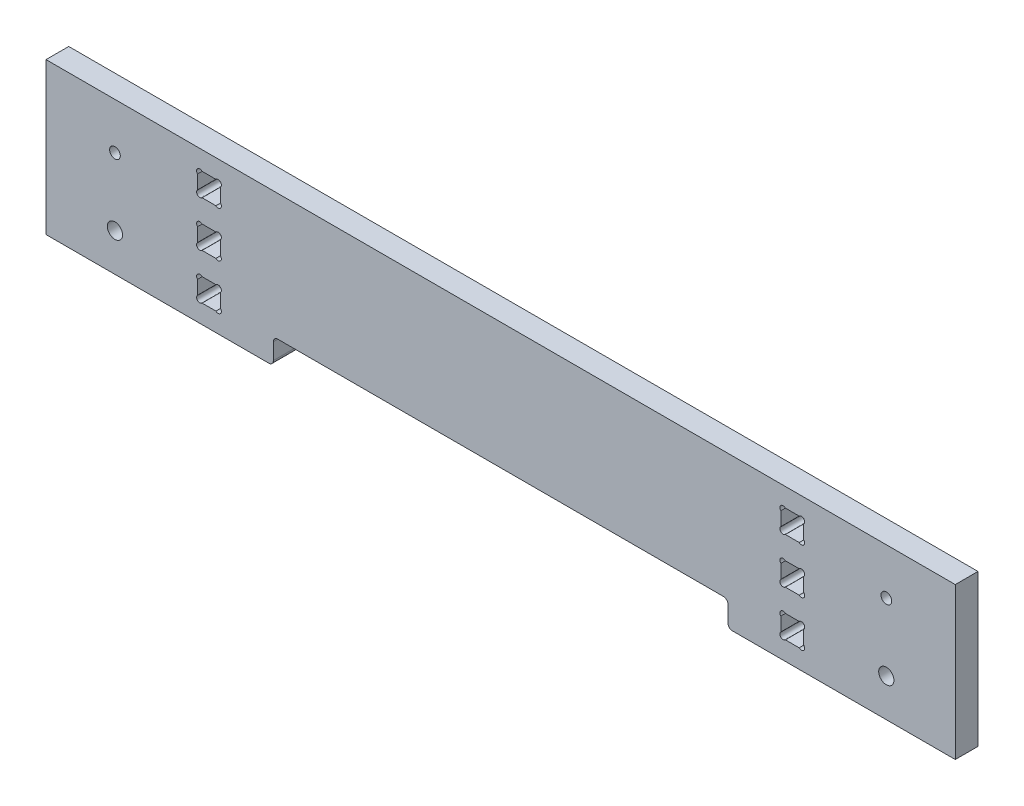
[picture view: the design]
ISO-10303-21;
HEADER;
FILE_DESCRIPTION(('STEP AP214'),'2;1');
FILE_NAME('part.step','',(''),(''),'','','');
FILE_SCHEMA(('AUTOMOTIVE_DESIGN { 1 0 10303 214 1 1 1 1 }'));
ENDSEC;
DATA;
#1=APPLICATION_CONTEXT('core data for automotive mechanical design processes');
#2=APPLICATION_PROTOCOL_DEFINITION('international standard','automotive_design',2000,#1);
#3=PRODUCT_CONTEXT('',#1,'mechanical');
#4=PRODUCT('Part','Part','',(#3));
#5=PRODUCT_RELATED_PRODUCT_CATEGORY('part','',(#4));
#6=PRODUCT_DEFINITION_FORMATION('','',#4);
#7=PRODUCT_DEFINITION_CONTEXT('part definition',#1,'design');
#8=PRODUCT_DEFINITION('design','',#6,#7);
#9=PRODUCT_DEFINITION_SHAPE('','',#8);
#10=(LENGTH_UNIT() NAMED_UNIT(*) SI_UNIT(.MILLI.,.METRE.));
#11=(NAMED_UNIT(*) PLANE_ANGLE_UNIT() SI_UNIT($,.RADIAN.));
#12=(NAMED_UNIT(*) SI_UNIT($,.STERADIAN.) SOLID_ANGLE_UNIT());
#13=UNCERTAINTY_MEASURE_WITH_UNIT(LENGTH_MEASURE(1.E-05),#10,'distance_accuracy_value','');
#14=(GEOMETRIC_REPRESENTATION_CONTEXT(3) GLOBAL_UNCERTAINTY_ASSIGNED_CONTEXT((#13)) GLOBAL_UNIT_ASSIGNED_CONTEXT((#10,
#11,#12)) REPRESENTATION_CONTEXT('',''));
#15=CARTESIAN_POINT('',(0.,0.,0.));
#16=DIRECTION('',(0.,0.,1.));
#17=DIRECTION('',(1.,0.,0.));
#18=AXIS2_PLACEMENT_3D('',#15,#16,#17);
#19=CARTESIAN_POINT('',(0.,0.,15.));
#20=DIRECTION('',(0.,0.,-1.));
#21=DIRECTION('',(-1.,0.,0.));
#22=AXIS2_PLACEMENT_3D('',#19,#20,#21);
#23=PLANE('',#22);
#24=CARTESIAN_POINT('',(45.5,25.,15.));
#25=DIRECTION('',(0.,0.,1.));
#26=DIRECTION('',(1.,0.,0.));
#27=AXIS2_PLACEMENT_3D('',#24,#25,#26);
#28=CIRCLE('',#27,5.025);
#29=CARTESIAN_POINT('',(50.5249999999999,25.,15.));
#30=VERTEX_POINT('',#29);
#31=EDGE_CURVE('E1713',#30,#30,#28,.T.);
#32=ORIENTED_EDGE('',*,*,#31,.F.);
#33=EDGE_LOOP('',(#32));
#34=FACE_BOUND('',#33,.T.);
#35=CARTESIAN_POINT('',(554.5,25.,15.));
#36=DIRECTION('',(0.,0.,1.));
#37=DIRECTION('',(1.,0.,0.));
#38=AXIS2_PLACEMENT_3D('',#35,#36,#37);
#39=CIRCLE('',#38,5.025);
#40=CARTESIAN_POINT('',(559.525,25.,15.));
#41=VERTEX_POINT('',#40);
#42=EDGE_CURVE('E1707',#41,#41,#39,.T.);
#43=ORIENTED_EDGE('',*,*,#42,.F.);
#44=EDGE_LOOP('',(#43));
#45=FACE_BOUND('',#44,.T.);
#46=CARTESIAN_POINT('',(554.5,69.5,15.));
#47=DIRECTION('',(0.,0.,1.));
#48=DIRECTION('',(1.,0.,0.));
#49=AXIS2_PLACEMENT_3D('',#46,#47,#48);
#50=CIRCLE('',#49,3.52500000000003);
#51=CARTESIAN_POINT('',(558.025,69.5,15.));
#52=VERTEX_POINT('',#51);
#53=EDGE_CURVE('E424',#52,#52,#50,.T.);
#54=ORIENTED_EDGE('',*,*,#53,.F.);
#55=EDGE_LOOP('',(#54));
#56=FACE_BOUND('',#55,.T.);
#57=DIRECTION('',(-1.,0.,0.));
#58=VECTOR('',#57,1.);
#59=CARTESIAN_POINT('',(112.1,27.4500000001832,15.));
#60=LINE('',#59,#58);
#61=CARTESIAN_POINT('',(112.1,27.4500000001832,15.));
#62=VERTEX_POINT('',#61);
#63=CARTESIAN_POINT('',(103.,27.4500000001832,15.));
#64=VERTEX_POINT('',#63);
#65=EDGE_CURVE('E438',#62,#64,#60,.T.);
#66=ORIENTED_EDGE('',*,*,#65,.F.);
#67=CARTESIAN_POINT('',(113.6,25.9500000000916,15.));
#68=DIRECTION('',(0.,0.,1.));
#69=DIRECTION('',(1.,0.,0.));
#70=AXIS2_PLACEMENT_3D('',#67,#68,#69);
#71=CIRCLE('',#70,2.12132034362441);
#72=CARTESIAN_POINT('',(115.1,24.45,15.));
#73=VERTEX_POINT('',#72);
#74=EDGE_CURVE('E416',#73,#62,#71,.T.);
#75=ORIENTED_EDGE('',*,*,#74,.F.);
#76=DIRECTION('',(0.,1.,0.));
#77=VECTOR('',#76,1.);
#78=CARTESIAN_POINT('',(115.1,15.35,15.));
#79=LINE('',#78,#77);
#80=CARTESIAN_POINT('',(115.1,15.35,15.));
#81=VERTEX_POINT('',#80);
#82=EDGE_CURVE('E427',#81,#73,#79,.T.);
#83=ORIENTED_EDGE('',*,*,#82,.F.);
#84=CARTESIAN_POINT('',(113.6,13.85,15.));
#85=DIRECTION('',(0.,0.,1.));
#86=DIRECTION('',(1.,0.,0.));
#87=AXIS2_PLACEMENT_3D('',#84,#85,#86);
#88=CIRCLE('',#87,2.12132034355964);
#89=CARTESIAN_POINT('',(112.1,12.35,15.));
#90=VERTEX_POINT('',#89);
#91=EDGE_CURVE('E432',#90,#81,#88,.T.);
#92=ORIENTED_EDGE('',*,*,#91,.F.);
#93=DIRECTION('',(1.,0.,0.));
#94=VECTOR('',#93,1.);
#95=CARTESIAN_POINT('',(103.,12.35,15.));
#96=LINE('',#95,#94);
#97=CARTESIAN_POINT('',(103.,12.35,15.));
#98=VERTEX_POINT('',#97);
#99=EDGE_CURVE('E1671',#98,#90,#96,.T.);
#100=ORIENTED_EDGE('',*,*,#99,.F.);
#101=CARTESIAN_POINT('',(101.5,13.85,15.));
#102=DIRECTION('',(0.,0.,1.));
#103=DIRECTION('',(1.,0.,0.));
#104=AXIS2_PLACEMENT_3D('',#101,#102,#103);
#105=CIRCLE('',#104,2.12132034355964);
#106=CARTESIAN_POINT('',(100.,15.35,15.));
#107=VERTEX_POINT('',#106);
#108=EDGE_CURVE('E1673',#107,#98,#105,.T.);
#109=ORIENTED_EDGE('',*,*,#108,.F.);
#110=DIRECTION('',(0.,-1.,0.));
#111=VECTOR('',#110,1.);
#112=CARTESIAN_POINT('',(100.,24.45,15.));
#113=LINE('',#112,#111);
#114=CARTESIAN_POINT('',(100.,24.45,15.));
#115=VERTEX_POINT('',#114);
#116=EDGE_CURVE('E1678',#115,#107,#113,.T.);
#117=ORIENTED_EDGE('',*,*,#116,.F.);
#118=CARTESIAN_POINT('',(101.5,25.9500000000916,15.));
#119=DIRECTION('',(0.,0.,-1.));
#120=DIRECTION('',(-1.,0.,0.));
#121=AXIS2_PLACEMENT_3D('',#118,#119,#120);
#122=CIRCLE('',#121,2.12132034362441);
#123=EDGE_CURVE('E443',#115,#64,#122,.T.);
#124=ORIENTED_EDGE('',*,*,#123,.T.);
#125=EDGE_LOOP('',(#66,#75,#83,#92,#100,#109,#117,#124));
#126=FACE_BOUND('',#125,.T.);
#127=CARTESIAN_POINT('',(113.6,43.9500000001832,15.));
#128=DIRECTION('',(0.,0.,1.));
#129=DIRECTION('',(1.,0.,0.));
#130=AXIS2_PLACEMENT_3D('',#127,#128,#129);
#131=CIRCLE('',#130,2.12132034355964);
#132=CARTESIAN_POINT('',(112.1,42.4500000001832,15.));
#133=VERTEX_POINT('',#132);
#134=CARTESIAN_POINT('',(115.1,45.4500000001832,15.));
#135=VERTEX_POINT('',#134);
#136=EDGE_CURVE('E503',#133,#135,#131,.T.);
#137=ORIENTED_EDGE('',*,*,#136,.F.);
#138=DIRECTION('',(1.,0.,0.));
#139=VECTOR('',#138,1.);
#140=CARTESIAN_POINT('',(103.,42.4500000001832,15.));
#141=LINE('',#140,#139);
#142=CARTESIAN_POINT('',(103.,42.4500000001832,15.));
#143=VERTEX_POINT('',#142);
#144=EDGE_CURVE('E506',#143,#133,#141,.T.);
#145=ORIENTED_EDGE('',*,*,#144,.F.);
#146=CARTESIAN_POINT('',(101.5,43.9500000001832,15.));
#147=DIRECTION('',(0.,0.,1.));
#148=DIRECTION('',(1.,0.,0.));
#149=AXIS2_PLACEMENT_3D('',#146,#147,#148);
#150=CIRCLE('',#149,2.12132034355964);
#151=CARTESIAN_POINT('',(100.,45.4500000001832,15.));
#152=VERTEX_POINT('',#151);
#153=EDGE_CURVE('E484',#152,#143,#150,.T.);
#154=ORIENTED_EDGE('',*,*,#153,.F.);
#155=DIRECTION('',(0.,-1.,0.));
#156=VECTOR('',#155,1.);
#157=CARTESIAN_POINT('',(100.,54.5500000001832,15.));
#158=LINE('',#157,#156);
#159=CARTESIAN_POINT('',(100.,54.5500000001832,15.));
#160=VERTEX_POINT('',#159);
#161=EDGE_CURVE('E487',#160,#152,#158,.T.);
#162=ORIENTED_EDGE('',*,*,#161,.F.);
#163=CARTESIAN_POINT('',(101.5,56.0500000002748,15.));
#164=DIRECTION('',(0.,0.,-1.));
#165=DIRECTION('',(-1.,0.,0.));
#166=AXIS2_PLACEMENT_3D('',#163,#164,#165);
#167=CIRCLE('',#166,2.1213203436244);
#168=CARTESIAN_POINT('',(103.,57.5500000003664,15.));
#169=VERTEX_POINT('',#168);
#170=EDGE_CURVE('E491',#160,#169,#167,.T.);
#171=ORIENTED_EDGE('',*,*,#170,.T.);
#172=DIRECTION('',(-1.,0.,0.));
#173=VECTOR('',#172,1.);
#174=CARTESIAN_POINT('',(112.1,57.5500000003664,15.));
#175=LINE('',#174,#173);
#176=CARTESIAN_POINT('',(112.1,57.5500000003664,15.));
#177=VERTEX_POINT('',#176);
#178=EDGE_CURVE('E494',#177,#169,#175,.T.);
#179=ORIENTED_EDGE('',*,*,#178,.F.);
#180=CARTESIAN_POINT('',(113.6,56.0500000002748,15.));
#181=DIRECTION('',(0.,0.,1.));
#182=DIRECTION('',(1.,0.,0.));
#183=AXIS2_PLACEMENT_3D('',#180,#181,#182);
#184=CIRCLE('',#183,2.12132034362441);
#185=CARTESIAN_POINT('',(115.1,54.5500000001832,15.));
#186=VERTEX_POINT('',#185);
#187=EDGE_CURVE('E497',#186,#177,#184,.T.);
#188=ORIENTED_EDGE('',*,*,#187,.F.);
#189=DIRECTION('',(0.,1.,0.));
#190=VECTOR('',#189,1.);
#191=CARTESIAN_POINT('',(115.1,45.4500000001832,15.));
#192=LINE('',#191,#190);
#193=EDGE_CURVE('E500',#135,#186,#192,.T.);
#194=ORIENTED_EDGE('',*,*,#193,.F.);
#195=EDGE_LOOP('',(#137,#145,#154,#162,#171,#179,#188,#194));
#196=FACE_BOUND('',#195,.T.);
#197=DIRECTION('',(1.,0.,0.));
#198=VECTOR('',#197,1.);
#199=CARTESIAN_POINT('',(103.,72.5500000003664,15.));
#200=LINE('',#199,#198);
#201=CARTESIAN_POINT('',(103.,72.5500000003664,15.));
#202=VERTEX_POINT('',#201);
#203=CARTESIAN_POINT('',(112.1,72.5500000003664,15.));
#204=VERTEX_POINT('',#203);
#205=EDGE_CURVE('E566',#202,#204,#200,.T.);
#206=ORIENTED_EDGE('',*,*,#205,.F.);
#207=CARTESIAN_POINT('',(101.5,74.0500000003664,15.));
#208=DIRECTION('',(0.,0.,1.));
#209=DIRECTION('',(1.,0.,0.));
#210=AXIS2_PLACEMENT_3D('',#207,#208,#209);
#211=CIRCLE('',#210,2.12132034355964);
#212=CARTESIAN_POINT('',(100.,75.5500000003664,15.));
#213=VERTEX_POINT('',#212);
#214=EDGE_CURVE('E569',#213,#202,#211,.T.);
#215=ORIENTED_EDGE('',*,*,#214,.F.);
#216=DIRECTION('',(0.,-1.,0.));
#217=VECTOR('',#216,1.);
#218=CARTESIAN_POINT('',(100.,84.6500000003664,15.));
#219=LINE('',#218,#217);
#220=CARTESIAN_POINT('',(100.,84.6500000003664,15.));
#221=VERTEX_POINT('',#220);
#222=EDGE_CURVE('E547',#221,#213,#219,.T.);
#223=ORIENTED_EDGE('',*,*,#222,.F.);
#224=CARTESIAN_POINT('',(101.5,86.150000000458,15.));
#225=DIRECTION('',(0.,0.,-1.));
#226=DIRECTION('',(-1.,0.,0.));
#227=AXIS2_PLACEMENT_3D('',#224,#225,#226);
#228=CIRCLE('',#227,2.12132034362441);
#229=CARTESIAN_POINT('',(103.,87.6500000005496,15.));
#230=VERTEX_POINT('',#229);
#231=EDGE_CURVE('E550',#221,#230,#228,.T.);
#232=ORIENTED_EDGE('',*,*,#231,.T.);
#233=DIRECTION('',(-1.,0.,0.));
#234=VECTOR('',#233,1.);
#235=CARTESIAN_POINT('',(112.1,87.6500000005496,15.));
#236=LINE('',#235,#234);
#237=CARTESIAN_POINT('',(112.1,87.6500000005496,15.));
#238=VERTEX_POINT('',#237);
#239=EDGE_CURVE('E554',#238,#230,#236,.T.);
#240=ORIENTED_EDGE('',*,*,#239,.F.);
#241=CARTESIAN_POINT('',(113.6,86.150000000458,15.));
#242=DIRECTION('',(0.,0.,1.));
#243=DIRECTION('',(1.,0.,0.));
#244=AXIS2_PLACEMENT_3D('',#241,#242,#243);
#245=CIRCLE('',#244,2.12132034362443);
#246=CARTESIAN_POINT('',(115.1,84.6500000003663,15.));
#247=VERTEX_POINT('',#246);
#248=EDGE_CURVE('E557',#247,#238,#245,.T.);
#249=ORIENTED_EDGE('',*,*,#248,.F.);
#250=DIRECTION('',(0.,1.,0.));
#251=VECTOR('',#250,1.);
#252=CARTESIAN_POINT('',(115.1,75.5500000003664,15.));
#253=LINE('',#252,#251);
#254=CARTESIAN_POINT('',(115.1,75.5500000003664,15.));
#255=VERTEX_POINT('',#254);
#256=EDGE_CURVE('E560',#255,#247,#253,.T.);
#257=ORIENTED_EDGE('',*,*,#256,.F.);
#258=CARTESIAN_POINT('',(113.6,74.0500000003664,15.));
#259=DIRECTION('',(0.,0.,1.));
#260=DIRECTION('',(1.,0.,0.));
#261=AXIS2_PLACEMENT_3D('',#258,#259,#260);
#262=CIRCLE('',#261,2.12132034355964);
#263=EDGE_CURVE('E563',#204,#255,#262,.T.);
#264=ORIENTED_EDGE('',*,*,#263,.F.);
#265=EDGE_LOOP('',(#206,#215,#223,#232,#240,#249,#257,#264));
#266=FACE_BOUND('',#265,.T.);
#267=CARTESIAN_POINT('',(45.5,69.5,15.));
#268=DIRECTION('',(0.,0.,1.));
#269=DIRECTION('',(1.,0.,0.));
#270=AXIS2_PLACEMENT_3D('',#267,#268,#269);
#271=CIRCLE('',#270,3.525);
#272=CARTESIAN_POINT('',(49.025,69.5,15.));
#273=VERTEX_POINT('',#272);
#274=EDGE_CURVE('E593',#273,#273,#271,.T.);
#275=ORIENTED_EDGE('',*,*,#274,.F.);
#276=EDGE_LOOP('',(#275));
#277=FACE_BOUND('',#276,.T.);
#278=CARTESIAN_POINT('',(498.5,56.0499999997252,15.));
#279=DIRECTION('',(0.,0.,1.));
#280=DIRECTION('',(1.,0.,0.));
#281=AXIS2_PLACEMENT_3D('',#278,#279,#280);
#282=CIRCLE('',#281,2.12132034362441);
#283=CARTESIAN_POINT('',(500.,54.5499999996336,15.));
#284=VERTEX_POINT('',#283);
#285=CARTESIAN_POINT('',(497.,57.5499999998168,15.));
#286=VERTEX_POINT('',#285);
#287=EDGE_CURVE('E635',#284,#286,#282,.T.);
#288=ORIENTED_EDGE('',*,*,#287,.F.);
#289=DIRECTION('',(0.,1.,0.));
#290=VECTOR('',#289,1.);
#291=CARTESIAN_POINT('',(500.,0.,15.));
#292=LINE('',#291,#290);
#293=CARTESIAN_POINT('',(500.,45.4499999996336,15.));
#294=VERTEX_POINT('',#293);
#295=EDGE_CURVE('E638',#294,#284,#292,.T.);
#296=ORIENTED_EDGE('',*,*,#295,.F.);
#297=CARTESIAN_POINT('',(498.5,43.9499999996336,15.));
#298=DIRECTION('',(0.,0.,1.));
#299=DIRECTION('',(1.,0.,0.));
#300=AXIS2_PLACEMENT_3D('',#297,#298,#299);
#301=CIRCLE('',#300,2.12132034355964);
#302=CARTESIAN_POINT('',(497.,42.4499999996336,15.));
#303=VERTEX_POINT('',#302);
#304=EDGE_CURVE('E616',#303,#294,#301,.T.);
#305=ORIENTED_EDGE('',*,*,#304,.F.);
#306=DIRECTION('',(1.,0.,0.));
#307=VECTOR('',#306,1.);
#308=CARTESIAN_POINT('',(0.,42.4499999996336,15.));
#309=LINE('',#308,#307);
#310=CARTESIAN_POINT('',(487.9,42.4499999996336,15.));
#311=VERTEX_POINT('',#310);
#312=EDGE_CURVE('E619',#311,#303,#309,.T.);
#313=ORIENTED_EDGE('',*,*,#312,.F.);
#314=CARTESIAN_POINT('',(486.4,43.9499999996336,15.));
#315=DIRECTION('',(0.,0.,1.));
#316=DIRECTION('',(1.,0.,0.));
#317=AXIS2_PLACEMENT_3D('',#314,#315,#316);
#318=CIRCLE('',#317,2.12132034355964);
#319=CARTESIAN_POINT('',(484.9,45.4499999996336,15.));
#320=VERTEX_POINT('',#319);
#321=EDGE_CURVE('E623',#320,#311,#318,.T.);
#322=ORIENTED_EDGE('',*,*,#321,.F.);
#323=DIRECTION('',(0.,-1.,0.));
#324=VECTOR('',#323,1.);
#325=CARTESIAN_POINT('',(484.9,0.,15.));
#326=LINE('',#325,#324);
#327=CARTESIAN_POINT('',(484.9,54.5499999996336,15.));
#328=VERTEX_POINT('',#327);
#329=EDGE_CURVE('E626',#328,#320,#326,.T.);
#330=ORIENTED_EDGE('',*,*,#329,.F.);
#331=CARTESIAN_POINT('',(486.4,56.0499999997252,15.));
#332=DIRECTION('',(0.,0.,1.));
#333=DIRECTION('',(1.,0.,0.));
#334=AXIS2_PLACEMENT_3D('',#331,#332,#333);
#335=CIRCLE('',#334,2.12132034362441);
#336=CARTESIAN_POINT('',(487.9,57.5499999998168,15.));
#337=VERTEX_POINT('',#336);
#338=EDGE_CURVE('E629',#328,#337,#335,.F.);
#339=ORIENTED_EDGE('',*,*,#338,.T.);
#340=DIRECTION('',(-1.,0.,0.));
#341=VECTOR('',#340,1.);
#342=CARTESIAN_POINT('',(0.,57.5499999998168,15.));
#343=LINE('',#342,#341);
#344=EDGE_CURVE('E632',#286,#337,#343,.T.);
#345=ORIENTED_EDGE('',*,*,#344,.F.);
#346=EDGE_LOOP('',(#288,#296,#305,#313,#322,#330,#339,#345));
#347=FACE_BOUND('',#346,.T.);
#348=CARTESIAN_POINT('',(498.5,25.9499999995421,15.));
#349=DIRECTION('',(0.,0.,1.));
#350=DIRECTION('',(1.,0.,0.));
#351=AXIS2_PLACEMENT_3D('',#348,#349,#350);
#352=CIRCLE('',#351,2.12132034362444);
#353=CARTESIAN_POINT('',(500.,24.4499999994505,15.));
#354=VERTEX_POINT('',#353);
#355=CARTESIAN_POINT('',(497.,27.4499999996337,15.));
#356=VERTEX_POINT('',#355);
#357=EDGE_CURVE('E698',#354,#356,#352,.T.);
#358=ORIENTED_EDGE('',*,*,#357,.F.);
#359=DIRECTION('',(0.,1.,0.));
#360=VECTOR('',#359,1.);
#361=CARTESIAN_POINT('',(500.,0.,15.));
#362=LINE('',#361,#360);
#363=CARTESIAN_POINT('',(500.,15.3499999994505,15.));
#364=VERTEX_POINT('',#363);
#365=EDGE_CURVE('E701',#364,#354,#362,.T.);
#366=ORIENTED_EDGE('',*,*,#365,.F.);
#367=CARTESIAN_POINT('',(498.5,13.8499999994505,15.));
#368=DIRECTION('',(0.,0.,1.));
#369=DIRECTION('',(1.,0.,0.));
#370=AXIS2_PLACEMENT_3D('',#367,#368,#369);
#371=CIRCLE('',#370,2.12132034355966);
#372=CARTESIAN_POINT('',(497.,12.3499999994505,15.));
#373=VERTEX_POINT('',#372);
#374=EDGE_CURVE('E679',#373,#364,#371,.T.);
#375=ORIENTED_EDGE('',*,*,#374,.F.);
#376=DIRECTION('',(1.,0.,0.));
#377=VECTOR('',#376,1.);
#378=CARTESIAN_POINT('',(0.,12.3499999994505,15.));
#379=LINE('',#378,#377);
#380=CARTESIAN_POINT('',(487.9,12.3499999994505,15.));
#381=VERTEX_POINT('',#380);
#382=EDGE_CURVE('E682',#381,#373,#379,.T.);
#383=ORIENTED_EDGE('',*,*,#382,.F.);
#384=CARTESIAN_POINT('',(486.4,13.8499999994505,15.));
#385=DIRECTION('',(0.,0.,1.));
#386=DIRECTION('',(1.,0.,0.));
#387=AXIS2_PLACEMENT_3D('',#384,#385,#386);
#388=CIRCLE('',#387,2.12132034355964);
#389=CARTESIAN_POINT('',(484.9,15.3499999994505,15.));
#390=VERTEX_POINT('',#389);
#391=EDGE_CURVE('E686',#390,#381,#388,.T.);
#392=ORIENTED_EDGE('',*,*,#391,.F.);
#393=DIRECTION('',(0.,-1.,0.));
#394=VECTOR('',#393,1.);
#395=CARTESIAN_POINT('',(484.9,0.,15.));
#396=LINE('',#395,#394);
#397=CARTESIAN_POINT('',(484.9,24.4499999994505,15.));
#398=VERTEX_POINT('',#397);
#399=EDGE_CURVE('E689',#398,#390,#396,.T.);
#400=ORIENTED_EDGE('',*,*,#399,.F.);
#401=CARTESIAN_POINT('',(486.4,25.9499999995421,15.));
#402=DIRECTION('',(0.,0.,1.));
#403=DIRECTION('',(1.,0.,0.));
#404=AXIS2_PLACEMENT_3D('',#401,#402,#403);
#405=CIRCLE('',#404,2.12132034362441);
#406=CARTESIAN_POINT('',(487.9,27.4499999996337,15.));
#407=VERTEX_POINT('',#406);
#408=EDGE_CURVE('E692',#398,#407,#405,.F.);
#409=ORIENTED_EDGE('',*,*,#408,.T.);
#410=DIRECTION('',(-1.,0.,0.));
#411=VECTOR('',#410,1.);
#412=CARTESIAN_POINT('',(0.,27.4499999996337,15.));
#413=LINE('',#412,#411);
#414=EDGE_CURVE('E695',#356,#407,#413,.T.);
#415=ORIENTED_EDGE('',*,*,#414,.F.);
#416=EDGE_LOOP('',(#358,#366,#375,#383,#392,#400,#409,#415));
#417=FACE_BOUND('',#416,.T.);
#418=DIRECTION('',(0.,-1.,0.));
#419=VECTOR('',#418,1.);
#420=CARTESIAN_POINT('',(450.,16.7043263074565,15.));
#421=LINE('',#420,#419);
#422=CARTESIAN_POINT('',(450.,13.7043263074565,15.));
#423=VERTEX_POINT('',#422);
#424=CARTESIAN_POINT('',(450.,3.,15.));
#425=VERTEX_POINT('',#424);
#426=EDGE_CURVE('E799',#423,#425,#421,.T.);
#427=ORIENTED_EDGE('',*,*,#426,.T.);
#428=CARTESIAN_POINT('',(453.,3.,15.));
#429=DIRECTION('',(0.,0.,-1.));
#430=DIRECTION('',(-1.,0.,0.));
#431=AXIS2_PLACEMENT_3D('',#428,#429,#430);
#432=CIRCLE('',#431,3.);
#433=CARTESIAN_POINT('',(453.,0.,15.));
#434=VERTEX_POINT('',#433);
#435=EDGE_CURVE('E856',#425,#434,#432,.F.);
#436=ORIENTED_EDGE('',*,*,#435,.T.);
#437=DIRECTION('',(1.,0.,0.));
#438=VECTOR('',#437,1.);
#439=CARTESIAN_POINT('',(450.,0.,15.));
#440=LINE('',#439,#438);
#441=CARTESIAN_POINT('',(600.,0.,15.));
#442=VERTEX_POINT('',#441);
#443=EDGE_CURVE('E802',#434,#442,#440,.T.);
#444=ORIENTED_EDGE('',*,*,#443,.T.);
#445=DIRECTION('',(0.,1.,0.));
#446=VECTOR('',#445,1.);
#447=CARTESIAN_POINT('',(600.,0.,15.));
#448=LINE('',#447,#446);
#449=CARTESIAN_POINT('',(600.,100.,15.));
#450=VERTEX_POINT('',#449);
#451=EDGE_CURVE('E804',#442,#450,#448,.T.);
#452=ORIENTED_EDGE('',*,*,#451,.T.);
#453=DIRECTION('',(-1.,0.,0.));
#454=VECTOR('',#453,1.);
#455=CARTESIAN_POINT('',(0.,100.,15.));
#456=LINE('',#455,#454);
#457=CARTESIAN_POINT('',(0.,100.,15.));
#458=VERTEX_POINT('',#457);
#459=EDGE_CURVE('E806',#450,#458,#456,.T.);
#460=ORIENTED_EDGE('',*,*,#459,.T.);
#461=DIRECTION('',(0.,-1.,0.));
#462=VECTOR('',#461,1.);
#463=CARTESIAN_POINT('',(0.,0.,15.));
#464=LINE('',#463,#462);
#465=CARTESIAN_POINT('',(0.,0.,15.));
#466=VERTEX_POINT('',#465);
#467=EDGE_CURVE('E788',#458,#466,#464,.T.);
#468=ORIENTED_EDGE('',*,*,#467,.T.);
#469=DIRECTION('',(1.,0.,0.));
#470=VECTOR('',#469,1.);
#471=CARTESIAN_POINT('',(0.,0.,15.));
#472=LINE('',#471,#470);
#473=CARTESIAN_POINT('',(147.,0.,15.));
#474=VERTEX_POINT('',#473);
#475=EDGE_CURVE('E791',#466,#474,#472,.T.);
#476=ORIENTED_EDGE('',*,*,#475,.T.);
#477=CARTESIAN_POINT('',(147.,3.,15.));
#478=DIRECTION('',(0.,0.,-1.));
#479=DIRECTION('',(-1.,0.,0.));
#480=AXIS2_PLACEMENT_3D('',#477,#478,#479);
#481=CIRCLE('',#480,3.);
#482=CARTESIAN_POINT('',(150.,3.,15.));
#483=VERTEX_POINT('',#482);
#484=EDGE_CURVE('E57',#474,#483,#481,.F.);
#485=ORIENTED_EDGE('',*,*,#484,.T.);
#486=DIRECTION('',(0.,1.,0.));
#487=VECTOR('',#486,1.);
#488=CARTESIAN_POINT('',(150.,0.,15.));
#489=LINE('',#488,#487);
#490=CARTESIAN_POINT('',(150.,13.7043263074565,15.));
#491=VERTEX_POINT('',#490);
#492=EDGE_CURVE('E794',#483,#491,#489,.T.);
#493=ORIENTED_EDGE('',*,*,#492,.T.);
#494=CARTESIAN_POINT('',(153.,13.7043263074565,15.));
#495=DIRECTION('',(0.,0.,-1.));
#496=DIRECTION('',(-1.,0.,0.));
#497=AXIS2_PLACEMENT_3D('',#494,#495,#496);
#498=CIRCLE('',#497,3.);
#499=CARTESIAN_POINT('',(153.,16.7043263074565,15.));
#500=VERTEX_POINT('',#499);
#501=EDGE_CURVE('E11',#491,#500,#498,.T.);
#502=ORIENTED_EDGE('',*,*,#501,.T.);
#503=DIRECTION('',(1.,0.,0.));
#504=VECTOR('',#503,1.);
#505=CARTESIAN_POINT('',(150.,16.7043263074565,15.));
#506=LINE('',#505,#504);
#507=CARTESIAN_POINT('',(447.,16.7043263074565,15.));
#508=VERTEX_POINT('',#507);
#509=EDGE_CURVE('E796',#500,#508,#506,.T.);
#510=ORIENTED_EDGE('',*,*,#509,.T.);
#511=CARTESIAN_POINT('',(447.,13.7043263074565,15.));
#512=DIRECTION('',(0.,0.,-1.));
#513=DIRECTION('',(-1.,0.,0.));
#514=AXIS2_PLACEMENT_3D('',#511,#512,#513);
#515=CIRCLE('',#514,3.);
#516=EDGE_CURVE('E866',#508,#423,#515,.T.);
#517=ORIENTED_EDGE('',*,*,#516,.T.);
#518=EDGE_LOOP('',(#427,#436,#444,#452,#460,#468,#476,#485,#493,#502,#510,#517));
#519=FACE_BOUND('',#518,.T.);
#520=DIRECTION('',(0.,-1.,0.));
#521=VECTOR('',#520,1.);
#522=CARTESIAN_POINT('',(500.,0.,15.));
#523=LINE('',#522,#521);
#524=CARTESIAN_POINT('',(500.,84.6499999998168,15.));
#525=VERTEX_POINT('',#524);
#526=CARTESIAN_POINT('',(500.,75.5499999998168,15.));
#527=VERTEX_POINT('',#526);
#528=EDGE_CURVE('E703',#525,#527,#523,.T.);
#529=ORIENTED_EDGE('',*,*,#528,.T.);
#530=CARTESIAN_POINT('',(498.5,74.0499999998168,15.));
#531=DIRECTION('',(0.,0.,1.));
#532=DIRECTION('',(1.,0.,0.));
#533=AXIS2_PLACEMENT_3D('',#530,#531,#532);
#534=CIRCLE('',#533,2.12132034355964);
#535=CARTESIAN_POINT('',(497.,72.5499999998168,15.));
#536=VERTEX_POINT('',#535);
#537=EDGE_CURVE('E728',#536,#527,#534,.T.);
#538=ORIENTED_EDGE('',*,*,#537,.F.);
#539=DIRECTION('',(1.,0.,0.));
#540=VECTOR('',#539,1.);
#541=CARTESIAN_POINT('',(0.,72.5499999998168,15.));
#542=LINE('',#541,#540);
#543=CARTESIAN_POINT('',(487.9,72.5499999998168,15.));
#544=VERTEX_POINT('',#543);
#545=EDGE_CURVE('E766',#544,#536,#542,.T.);
#546=ORIENTED_EDGE('',*,*,#545,.F.);
#547=CARTESIAN_POINT('',(486.4,74.0499999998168,15.));
#548=DIRECTION('',(0.,0.,1.));
#549=DIRECTION('',(1.,0.,0.));
#550=AXIS2_PLACEMENT_3D('',#547,#548,#549);
#551=CIRCLE('',#550,2.12132034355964);
#552=CARTESIAN_POINT('',(484.9,75.5499999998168,15.));
#553=VERTEX_POINT('',#552);
#554=EDGE_CURVE('E763',#553,#544,#551,.T.);
#555=ORIENTED_EDGE('',*,*,#554,.F.);
#556=DIRECTION('',(0.,-1.,0.));
#557=VECTOR('',#556,1.);
#558=CARTESIAN_POINT('',(484.9,0.,15.));
#559=LINE('',#558,#557);
#560=CARTESIAN_POINT('',(484.9,84.6499999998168,15.));
#561=VERTEX_POINT('',#560);
#562=EDGE_CURVE('E760',#561,#553,#559,.T.);
#563=ORIENTED_EDGE('',*,*,#562,.F.);
#564=CARTESIAN_POINT('',(486.4,86.1499999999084,15.));
#565=DIRECTION('',(0.,0.,1.));
#566=DIRECTION('',(1.,0.,0.));
#567=AXIS2_PLACEMENT_3D('',#564,#565,#566);
#568=CIRCLE('',#567,2.12132034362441);
#569=CARTESIAN_POINT('',(487.9,87.65,15.));
#570=VERTEX_POINT('',#569);
#571=EDGE_CURVE('E757',#561,#570,#568,.F.);
#572=ORIENTED_EDGE('',*,*,#571,.T.);
#573=DIRECTION('',(-1.,0.,0.));
#574=VECTOR('',#573,1.);
#575=CARTESIAN_POINT('',(0.,87.65,15.));
#576=LINE('',#575,#574);
#577=CARTESIAN_POINT('',(497.,87.65,15.));
#578=VERTEX_POINT('',#577);
#579=EDGE_CURVE('E754',#578,#570,#576,.T.);
#580=ORIENTED_EDGE('',*,*,#579,.F.);
#581=CARTESIAN_POINT('',(498.5,86.1499999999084,15.));
#582=DIRECTION('',(0.,0.,1.));
#583=DIRECTION('',(1.,0.,0.));
#584=AXIS2_PLACEMENT_3D('',#581,#582,#583);
#585=CIRCLE('',#584,2.12132034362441);
#586=EDGE_CURVE('E751',#525,#578,#585,.T.);
#587=ORIENTED_EDGE('',*,*,#586,.F.);
#588=EDGE_LOOP('',(#529,#538,#546,#555,#563,#572,#580,#587));
#589=FACE_BOUND('',#588,.T.);
#590=ADVANCED_FACE('F35',(#34,#45,#56,#126,#196,#266,#277,#347,#417,#519,#589),#23,.F.);
#591=CARTESIAN_POINT('',(0.,0.,0.));
#592=DIRECTION('',(0.,0.,-1.));
#593=DIRECTION('',(-1.,0.,0.));
#594=AXIS2_PLACEMENT_3D('',#591,#592,#593);
#595=PLANE('',#594);
#596=CARTESIAN_POINT('',(554.5,69.5,0.));
#597=DIRECTION('',(0.,0.,1.));
#598=DIRECTION('',(1.,0.,0.));
#599=AXIS2_PLACEMENT_3D('',#596,#597,#598);
#600=CIRCLE('',#599,3.52500000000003);
#601=CARTESIAN_POINT('',(558.025,69.5,0.));
#602=VERTEX_POINT('',#601);
#603=EDGE_CURVE('E1691',#602,#602,#600,.T.);
#604=ORIENTED_EDGE('',*,*,#603,.T.);
#605=EDGE_LOOP('',(#604));
#606=FACE_BOUND('',#605,.T.);
#607=CARTESIAN_POINT('',(113.6,25.9500000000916,0.));
#608=DIRECTION('',(0.,0.,1.));
#609=DIRECTION('',(1.,0.,0.));
#610=AXIS2_PLACEMENT_3D('',#607,#608,#609);
#611=CIRCLE('',#610,2.12132034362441);
#612=CARTESIAN_POINT('',(115.1,24.45,0.));
#613=VERTEX_POINT('',#612);
#614=CARTESIAN_POINT('',(112.1,27.4500000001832,0.));
#615=VERTEX_POINT('',#614);
#616=EDGE_CURVE('E419',#613,#615,#611,.T.);
#617=ORIENTED_EDGE('',*,*,#616,.T.);
#618=DIRECTION('',(-1.,0.,0.));
#619=VECTOR('',#618,1.);
#620=CARTESIAN_POINT('',(112.1,27.4500000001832,0.));
#621=LINE('',#620,#619);
#622=CARTESIAN_POINT('',(103.,27.4500000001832,0.));
#623=VERTEX_POINT('',#622);
#624=EDGE_CURVE('E465',#615,#623,#621,.T.);
#625=ORIENTED_EDGE('',*,*,#624,.T.);
#626=CARTESIAN_POINT('',(101.5,25.9500000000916,0.));
#627=DIRECTION('',(0.,0.,-1.));
#628=DIRECTION('',(-1.,0.,0.));
#629=AXIS2_PLACEMENT_3D('',#626,#627,#628);
#630=CIRCLE('',#629,2.12132034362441);
#631=CARTESIAN_POINT('',(100.,24.45,0.));
#632=VERTEX_POINT('',#631);
#633=EDGE_CURVE('E462',#632,#623,#630,.T.);
#634=ORIENTED_EDGE('',*,*,#633,.F.);
#635=DIRECTION('',(0.,-1.,0.));
#636=VECTOR('',#635,1.);
#637=CARTESIAN_POINT('',(100.,24.45,0.));
#638=LINE('',#637,#636);
#639=CARTESIAN_POINT('',(100.,15.35,0.));
#640=VERTEX_POINT('',#639);
#641=EDGE_CURVE('E459',#632,#640,#638,.T.);
#642=ORIENTED_EDGE('',*,*,#641,.T.);
#643=CARTESIAN_POINT('',(101.5,13.85,0.));
#644=DIRECTION('',(0.,0.,1.));
#645=DIRECTION('',(1.,0.,0.));
#646=AXIS2_PLACEMENT_3D('',#643,#644,#645);
#647=CIRCLE('',#646,2.12132034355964);
#648=CARTESIAN_POINT('',(103.,12.35,0.));
#649=VERTEX_POINT('',#648);
#650=EDGE_CURVE('E456',#640,#649,#647,.T.);
#651=ORIENTED_EDGE('',*,*,#650,.T.);
#652=DIRECTION('',(1.,0.,0.));
#653=VECTOR('',#652,1.);
#654=CARTESIAN_POINT('',(103.,12.35,0.));
#655=LINE('',#654,#653);
#656=CARTESIAN_POINT('',(112.1,12.35,0.));
#657=VERTEX_POINT('',#656);
#658=EDGE_CURVE('E453',#649,#657,#655,.T.);
#659=ORIENTED_EDGE('',*,*,#658,.T.);
#660=CARTESIAN_POINT('',(113.6,13.85,0.));
#661=DIRECTION('',(0.,0.,1.));
#662=DIRECTION('',(1.,0.,0.));
#663=AXIS2_PLACEMENT_3D('',#660,#661,#662);
#664=CIRCLE('',#663,2.12132034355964);
#665=CARTESIAN_POINT('',(115.1,15.35,0.));
#666=VERTEX_POINT('',#665);
#667=EDGE_CURVE('E449',#657,#666,#664,.T.);
#668=ORIENTED_EDGE('',*,*,#667,.T.);
#669=DIRECTION('',(0.,1.,0.));
#670=VECTOR('',#669,1.);
#671=CARTESIAN_POINT('',(115.1,15.35,0.));
#672=LINE('',#671,#670);
#673=EDGE_CURVE('E447',#666,#613,#672,.T.);
#674=ORIENTED_EDGE('',*,*,#673,.T.);
#675=EDGE_LOOP('',(#617,#625,#634,#642,#651,#659,#668,#674));
#676=FACE_BOUND('',#675,.T.);
#677=DIRECTION('',(1.,0.,0.));
#678=VECTOR('',#677,1.);
#679=CARTESIAN_POINT('',(103.,42.4500000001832,0.));
#680=LINE('',#679,#678);
#681=CARTESIAN_POINT('',(103.,42.4500000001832,0.));
#682=VERTEX_POINT('',#681);
#683=CARTESIAN_POINT('',(112.1,42.4500000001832,0.));
#684=VERTEX_POINT('',#683);
#685=EDGE_CURVE('E488',#682,#684,#680,.T.);
#686=ORIENTED_EDGE('',*,*,#685,.T.);
#687=CARTESIAN_POINT('',(113.6,43.9500000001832,0.));
#688=DIRECTION('',(0.,0.,1.));
#689=DIRECTION('',(1.,0.,0.));
#690=AXIS2_PLACEMENT_3D('',#687,#688,#689);
#691=CIRCLE('',#690,2.12132034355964);
#692=CARTESIAN_POINT('',(115.1,45.4500000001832,0.));
#693=VERTEX_POINT('',#692);
#694=EDGE_CURVE('E525',#684,#693,#691,.T.);
#695=ORIENTED_EDGE('',*,*,#694,.T.);
#696=DIRECTION('',(0.,1.,0.));
#697=VECTOR('',#696,1.);
#698=CARTESIAN_POINT('',(115.1,45.4500000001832,0.));
#699=LINE('',#698,#697);
#700=CARTESIAN_POINT('',(115.1,54.5500000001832,0.));
#701=VERTEX_POINT('',#700);
#702=EDGE_CURVE('E522',#693,#701,#699,.T.);
#703=ORIENTED_EDGE('',*,*,#702,.T.);
#704=CARTESIAN_POINT('',(113.6,56.0500000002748,0.));
#705=DIRECTION('',(0.,0.,1.));
#706=DIRECTION('',(1.,0.,0.));
#707=AXIS2_PLACEMENT_3D('',#704,#705,#706);
#708=CIRCLE('',#707,2.12132034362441);
#709=CARTESIAN_POINT('',(112.1,57.5500000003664,0.));
#710=VERTEX_POINT('',#709);
#711=EDGE_CURVE('E519',#701,#710,#708,.T.);
#712=ORIENTED_EDGE('',*,*,#711,.T.);
#713=DIRECTION('',(-1.,0.,0.));
#714=VECTOR('',#713,1.);
#715=CARTESIAN_POINT('',(112.1,57.5500000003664,0.));
#716=LINE('',#715,#714);
#717=CARTESIAN_POINT('',(103.,57.5500000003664,0.));
#718=VERTEX_POINT('',#717);
#719=EDGE_CURVE('E516',#710,#718,#716,.T.);
#720=ORIENTED_EDGE('',*,*,#719,.T.);
#721=CARTESIAN_POINT('',(101.5,56.0500000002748,0.));
#722=DIRECTION('',(0.,0.,-1.));
#723=DIRECTION('',(-1.,0.,0.));
#724=AXIS2_PLACEMENT_3D('',#721,#722,#723);
#725=CIRCLE('',#724,2.1213203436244);
#726=CARTESIAN_POINT('',(100.,54.5500000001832,0.));
#727=VERTEX_POINT('',#726);
#728=EDGE_CURVE('E514',#727,#718,#725,.T.);
#729=ORIENTED_EDGE('',*,*,#728,.F.);
#730=DIRECTION('',(0.,-1.,0.));
#731=VECTOR('',#730,1.);
#732=CARTESIAN_POINT('',(100.,54.5500000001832,0.));
#733=LINE('',#732,#731);
#734=CARTESIAN_POINT('',(100.,45.4500000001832,0.));
#735=VERTEX_POINT('',#734);
#736=EDGE_CURVE('E511',#727,#735,#733,.T.);
#737=ORIENTED_EDGE('',*,*,#736,.T.);
#738=CARTESIAN_POINT('',(101.5,43.9500000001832,0.));
#739=DIRECTION('',(0.,0.,1.));
#740=DIRECTION('',(1.,0.,0.));
#741=AXIS2_PLACEMENT_3D('',#738,#739,#740);
#742=CIRCLE('',#741,2.12132034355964);
#743=EDGE_CURVE('E472',#735,#682,#742,.T.);
#744=ORIENTED_EDGE('',*,*,#743,.T.);
#745=EDGE_LOOP('',(#686,#695,#703,#712,#720,#729,#737,#744));
#746=FACE_BOUND('',#745,.T.);
#747=CARTESIAN_POINT('',(101.5,74.0500000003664,0.));
#748=DIRECTION('',(0.,0.,1.));
#749=DIRECTION('',(1.,0.,0.));
#750=AXIS2_PLACEMENT_3D('',#747,#748,#749);
#751=CIRCLE('',#750,2.12132034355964);
#752=CARTESIAN_POINT('',(100.,75.5500000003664,0.));
#753=VERTEX_POINT('',#752);
#754=CARTESIAN_POINT('',(103.,72.5500000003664,0.));
#755=VERTEX_POINT('',#754);
#756=EDGE_CURVE('E551',#753,#755,#751,.T.);
#757=ORIENTED_EDGE('',*,*,#756,.T.);
#758=DIRECTION('',(1.,0.,0.));
#759=VECTOR('',#758,1.);
#760=CARTESIAN_POINT('',(103.,72.5500000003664,0.));
#761=LINE('',#760,#759);
#762=CARTESIAN_POINT('',(112.1,72.5500000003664,0.));
#763=VERTEX_POINT('',#762);
#764=EDGE_CURVE('E588',#755,#763,#761,.T.);
#765=ORIENTED_EDGE('',*,*,#764,.T.);
#766=CARTESIAN_POINT('',(113.6,74.0500000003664,0.));
#767=DIRECTION('',(0.,0.,1.));
#768=DIRECTION('',(1.,0.,0.));
#769=AXIS2_PLACEMENT_3D('',#766,#767,#768);
#770=CIRCLE('',#769,2.12132034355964);
#771=CARTESIAN_POINT('',(115.1,75.5500000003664,0.));
#772=VERTEX_POINT('',#771);
#773=EDGE_CURVE('E585',#763,#772,#770,.T.);
#774=ORIENTED_EDGE('',*,*,#773,.T.);
#775=DIRECTION('',(0.,1.,0.));
#776=VECTOR('',#775,1.);
#777=CARTESIAN_POINT('',(115.1,75.5500000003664,0.));
#778=LINE('',#777,#776);
#779=CARTESIAN_POINT('',(115.1,84.6500000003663,0.));
#780=VERTEX_POINT('',#779);
#781=EDGE_CURVE('E582',#772,#780,#778,.T.);
#782=ORIENTED_EDGE('',*,*,#781,.T.);
#783=CARTESIAN_POINT('',(113.6,86.150000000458,0.));
#784=DIRECTION('',(0.,0.,1.));
#785=DIRECTION('',(1.,0.,0.));
#786=AXIS2_PLACEMENT_3D('',#783,#784,#785);
#787=CIRCLE('',#786,2.12132034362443);
#788=CARTESIAN_POINT('',(112.1,87.6500000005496,0.));
#789=VERTEX_POINT('',#788);
#790=EDGE_CURVE('E579',#780,#789,#787,.T.);
#791=ORIENTED_EDGE('',*,*,#790,.T.);
#792=DIRECTION('',(-1.,0.,0.));
#793=VECTOR('',#792,1.);
#794=CARTESIAN_POINT('',(112.1,87.6500000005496,0.));
#795=LINE('',#794,#793);
#796=CARTESIAN_POINT('',(103.,87.6500000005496,0.));
#797=VERTEX_POINT('',#796);
#798=EDGE_CURVE('E576',#789,#797,#795,.T.);
#799=ORIENTED_EDGE('',*,*,#798,.T.);
#800=CARTESIAN_POINT('',(101.5,86.150000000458,0.));
#801=DIRECTION('',(0.,0.,-1.));
#802=DIRECTION('',(-1.,0.,0.));
#803=AXIS2_PLACEMENT_3D('',#800,#801,#802);
#804=CIRCLE('',#803,2.12132034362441);
#805=CARTESIAN_POINT('',(100.,84.6500000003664,0.));
#806=VERTEX_POINT('',#805);
#807=EDGE_CURVE('E574',#806,#797,#804,.T.);
#808=ORIENTED_EDGE('',*,*,#807,.F.);
#809=DIRECTION('',(0.,-1.,0.));
#810=VECTOR('',#809,1.);
#811=CARTESIAN_POINT('',(100.,84.6500000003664,0.));
#812=LINE('',#811,#810);
#813=EDGE_CURVE('E533',#806,#753,#812,.T.);
#814=ORIENTED_EDGE('',*,*,#813,.T.);
#815=EDGE_LOOP('',(#757,#765,#774,#782,#791,#799,#808,#814));
#816=FACE_BOUND('',#815,.T.);
#817=CARTESIAN_POINT('',(45.5,69.5,0.));
#818=DIRECTION('',(0.,0.,1.));
#819=DIRECTION('',(1.,0.,0.));
#820=AXIS2_PLACEMENT_3D('',#817,#818,#819);
#821=CIRCLE('',#820,3.525);
#822=CARTESIAN_POINT('',(49.025,69.5,0.));
#823=VERTEX_POINT('',#822);
#824=EDGE_CURVE('E571',#823,#823,#821,.T.);
#825=ORIENTED_EDGE('',*,*,#824,.T.);
#826=EDGE_LOOP('',(#825));
#827=FACE_BOUND('',#826,.T.);
#828=DIRECTION('',(0.,1.,0.));
#829=VECTOR('',#828,1.);
#830=CARTESIAN_POINT('',(500.,0.,0.));
#831=LINE('',#830,#829);
#832=CARTESIAN_POINT('',(500.,45.4499999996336,0.));
#833=VERTEX_POINT('',#832);
#834=CARTESIAN_POINT('',(500.,54.5499999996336,0.));
#835=VERTEX_POINT('',#834);
#836=EDGE_CURVE('E620',#833,#835,#831,.T.);
#837=ORIENTED_EDGE('',*,*,#836,.T.);
#838=CARTESIAN_POINT('',(498.5,56.0499999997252,0.));
#839=DIRECTION('',(0.,0.,1.));
#840=DIRECTION('',(1.,0.,0.));
#841=AXIS2_PLACEMENT_3D('',#838,#839,#840);
#842=CIRCLE('',#841,2.12132034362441);
#843=CARTESIAN_POINT('',(497.,57.5499999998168,0.));
#844=VERTEX_POINT('',#843);
#845=EDGE_CURVE('E657',#835,#844,#842,.T.);
#846=ORIENTED_EDGE('',*,*,#845,.T.);
#847=DIRECTION('',(-1.,0.,0.));
#848=VECTOR('',#847,1.);
#849=CARTESIAN_POINT('',(0.,57.5499999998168,0.));
#850=LINE('',#849,#848);
#851=CARTESIAN_POINT('',(487.9,57.5499999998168,0.));
#852=VERTEX_POINT('',#851);
#853=EDGE_CURVE('E654',#844,#852,#850,.T.);
#854=ORIENTED_EDGE('',*,*,#853,.T.);
#855=CARTESIAN_POINT('',(486.4,56.0499999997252,0.));
#856=DIRECTION('',(0.,0.,1.));
#857=DIRECTION('',(1.,0.,0.));
#858=AXIS2_PLACEMENT_3D('',#855,#856,#857);
#859=CIRCLE('',#858,2.12132034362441);
#860=CARTESIAN_POINT('',(484.9,54.5499999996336,0.));
#861=VERTEX_POINT('',#860);
#862=EDGE_CURVE('E652',#861,#852,#859,.F.);
#863=ORIENTED_EDGE('',*,*,#862,.F.);
#864=DIRECTION('',(0.,-1.,0.));
#865=VECTOR('',#864,1.);
#866=CARTESIAN_POINT('',(484.9,0.,0.));
#867=LINE('',#866,#865);
#868=CARTESIAN_POINT('',(484.9,45.4499999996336,0.));
#869=VERTEX_POINT('',#868);
#870=EDGE_CURVE('E649',#861,#869,#867,.T.);
#871=ORIENTED_EDGE('',*,*,#870,.T.);
#872=CARTESIAN_POINT('',(486.4,43.9499999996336,0.));
#873=DIRECTION('',(0.,0.,1.));
#874=DIRECTION('',(1.,0.,0.));
#875=AXIS2_PLACEMENT_3D('',#872,#873,#874);
#876=CIRCLE('',#875,2.12132034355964);
#877=CARTESIAN_POINT('',(487.9,42.4499999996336,0.));
#878=VERTEX_POINT('',#877);
#879=EDGE_CURVE('E646',#869,#878,#876,.T.);
#880=ORIENTED_EDGE('',*,*,#879,.T.);
#881=DIRECTION('',(1.,0.,0.));
#882=VECTOR('',#881,1.);
#883=CARTESIAN_POINT('',(0.,42.4499999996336,0.));
#884=LINE('',#883,#882);
#885=CARTESIAN_POINT('',(497.,42.4499999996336,0.));
#886=VERTEX_POINT('',#885);
#887=EDGE_CURVE('E643',#878,#886,#884,.T.);
#888=ORIENTED_EDGE('',*,*,#887,.T.);
#889=CARTESIAN_POINT('',(498.5,43.9499999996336,0.));
#890=DIRECTION('',(0.,0.,1.));
#891=DIRECTION('',(1.,0.,0.));
#892=AXIS2_PLACEMENT_3D('',#889,#890,#891);
#893=CIRCLE('',#892,2.12132034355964);
#894=EDGE_CURVE('E602',#886,#833,#893,.T.);
#895=ORIENTED_EDGE('',*,*,#894,.T.);
#896=EDGE_LOOP('',(#837,#846,#854,#863,#871,#880,#888,#895));
#897=FACE_BOUND('',#896,.T.);
#898=DIRECTION('',(0.,1.,0.));
#899=VECTOR('',#898,1.);
#900=CARTESIAN_POINT('',(500.,0.,0.));
#901=LINE('',#900,#899);
#902=CARTESIAN_POINT('',(500.,15.3499999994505,0.));
#903=VERTEX_POINT('',#902);
#904=CARTESIAN_POINT('',(500.,24.4499999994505,0.));
#905=VERTEX_POINT('',#904);
#906=EDGE_CURVE('E683',#903,#905,#901,.T.);
#907=ORIENTED_EDGE('',*,*,#906,.T.);
#908=CARTESIAN_POINT('',(498.5,25.9499999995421,0.));
#909=DIRECTION('',(0.,0.,1.));
#910=DIRECTION('',(1.,0.,0.));
#911=AXIS2_PLACEMENT_3D('',#908,#909,#910);
#912=CIRCLE('',#911,2.12132034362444);
#913=CARTESIAN_POINT('',(497.,27.4499999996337,0.));
#914=VERTEX_POINT('',#913);
#915=EDGE_CURVE('E720',#905,#914,#912,.T.);
#916=ORIENTED_EDGE('',*,*,#915,.T.);
#917=DIRECTION('',(-1.,0.,0.));
#918=VECTOR('',#917,1.);
#919=CARTESIAN_POINT('',(0.,27.4499999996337,0.));
#920=LINE('',#919,#918);
#921=CARTESIAN_POINT('',(487.9,27.4499999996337,0.));
#922=VERTEX_POINT('',#921);
#923=EDGE_CURVE('E717',#914,#922,#920,.T.);
#924=ORIENTED_EDGE('',*,*,#923,.T.);
#925=CARTESIAN_POINT('',(486.4,25.9499999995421,0.));
#926=DIRECTION('',(0.,0.,1.));
#927=DIRECTION('',(1.,0.,0.));
#928=AXIS2_PLACEMENT_3D('',#925,#926,#927);
#929=CIRCLE('',#928,2.12132034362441);
#930=CARTESIAN_POINT('',(484.9,24.4499999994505,0.));
#931=VERTEX_POINT('',#930);
#932=EDGE_CURVE('E715',#931,#922,#929,.F.);
#933=ORIENTED_EDGE('',*,*,#932,.F.);
#934=DIRECTION('',(0.,-1.,0.));
#935=VECTOR('',#934,1.);
#936=CARTESIAN_POINT('',(484.9,0.,0.));
#937=LINE('',#936,#935);
#938=CARTESIAN_POINT('',(484.9,15.3499999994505,0.));
#939=VERTEX_POINT('',#938);
#940=EDGE_CURVE('E712',#931,#939,#937,.T.);
#941=ORIENTED_EDGE('',*,*,#940,.T.);
#942=CARTESIAN_POINT('',(486.4,13.8499999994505,0.));
#943=DIRECTION('',(0.,0.,1.));
#944=DIRECTION('',(1.,0.,0.));
#945=AXIS2_PLACEMENT_3D('',#942,#943,#944);
#946=CIRCLE('',#945,2.12132034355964);
#947=CARTESIAN_POINT('',(487.9,12.3499999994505,0.));
#948=VERTEX_POINT('',#947);
#949=EDGE_CURVE('E709',#939,#948,#946,.T.);
#950=ORIENTED_EDGE('',*,*,#949,.T.);
#951=DIRECTION('',(1.,0.,0.));
#952=VECTOR('',#951,1.);
#953=CARTESIAN_POINT('',(0.,12.3499999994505,0.));
#954=LINE('',#953,#952);
#955=CARTESIAN_POINT('',(497.,12.3499999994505,0.));
#956=VERTEX_POINT('',#955);
#957=EDGE_CURVE('E706',#948,#956,#954,.T.);
#958=ORIENTED_EDGE('',*,*,#957,.T.);
#959=CARTESIAN_POINT('',(498.5,13.8499999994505,0.));
#960=DIRECTION('',(0.,0.,1.));
#961=DIRECTION('',(1.,0.,0.));
#962=AXIS2_PLACEMENT_3D('',#959,#960,#961);
#963=CIRCLE('',#962,2.12132034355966);
#964=EDGE_CURVE('E665',#956,#903,#963,.T.);
#965=ORIENTED_EDGE('',*,*,#964,.T.);
#966=EDGE_LOOP('',(#907,#916,#924,#933,#941,#950,#958,#965));
#967=FACE_BOUND('',#966,.T.);
#968=DIRECTION('',(1.,0.,0.));
#969=VECTOR('',#968,1.);
#970=CARTESIAN_POINT('',(450.,0.,0.));
#971=LINE('',#970,#969);
#972=CARTESIAN_POINT('',(453.,0.,0.));
#973=VERTEX_POINT('',#972);
#974=CARTESIAN_POINT('',(600.,0.,0.));
#975=VERTEX_POINT('',#974);
#976=EDGE_CURVE('E822',#973,#975,#971,.T.);
#977=ORIENTED_EDGE('',*,*,#976,.F.);
#978=CARTESIAN_POINT('',(453.,3.,0.));
#979=DIRECTION('',(0.,0.,-1.));
#980=DIRECTION('',(-1.,0.,0.));
#981=AXIS2_PLACEMENT_3D('',#978,#979,#980);
#982=CIRCLE('',#981,3.);
#983=CARTESIAN_POINT('',(450.,3.,0.));
#984=VERTEX_POINT('',#983);
#985=EDGE_CURVE('E853',#973,#984,#982,.T.);
#986=ORIENTED_EDGE('',*,*,#985,.T.);
#987=DIRECTION('',(0.,-1.,0.));
#988=VECTOR('',#987,1.);
#989=CARTESIAN_POINT('',(450.,16.7043263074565,0.));
#990=LINE('',#989,#988);
#991=CARTESIAN_POINT('',(450.,13.7043263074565,0.));
#992=VERTEX_POINT('',#991);
#993=EDGE_CURVE('E819',#992,#984,#990,.T.);
#994=ORIENTED_EDGE('',*,*,#993,.F.);
#995=CARTESIAN_POINT('',(447.,13.7043263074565,0.));
#996=DIRECTION('',(0.,0.,-1.));
#997=DIRECTION('',(-1.,0.,0.));
#998=AXIS2_PLACEMENT_3D('',#995,#996,#997);
#999=CIRCLE('',#998,3.);
#1000=CARTESIAN_POINT('',(447.,16.7043263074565,0.));
#1001=VERTEX_POINT('',#1000);
#1002=EDGE_CURVE('E864',#992,#1001,#999,.F.);
#1003=ORIENTED_EDGE('',*,*,#1002,.T.);
#1004=DIRECTION('',(1.,0.,0.));
#1005=VECTOR('',#1004,1.);
#1006=CARTESIAN_POINT('',(150.,16.7043263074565,0.));
#1007=LINE('',#1006,#1005);
#1008=CARTESIAN_POINT('',(153.,16.7043263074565,0.));
#1009=VERTEX_POINT('',#1008);
#1010=EDGE_CURVE('E816',#1009,#1001,#1007,.T.);
#1011=ORIENTED_EDGE('',*,*,#1010,.F.);
#1012=CARTESIAN_POINT('',(153.,13.7043263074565,0.));
#1013=DIRECTION('',(0.,0.,-1.));
#1014=DIRECTION('',(-1.,0.,0.));
#1015=AXIS2_PLACEMENT_3D('',#1012,#1013,#1014);
#1016=CIRCLE('',#1015,3.);
#1017=CARTESIAN_POINT('',(150.,13.7043263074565,0.));
#1018=VERTEX_POINT('',#1017);
#1019=EDGE_CURVE('E43',#1009,#1018,#1016,.F.);
#1020=ORIENTED_EDGE('',*,*,#1019,.T.);
#1021=DIRECTION('',(0.,1.,0.));
#1022=VECTOR('',#1021,1.);
#1023=CARTESIAN_POINT('',(150.,0.,0.));
#1024=LINE('',#1023,#1022);
#1025=CARTESIAN_POINT('',(150.,3.,0.));
#1026=VERTEX_POINT('',#1025);
#1027=EDGE_CURVE('E814',#1026,#1018,#1024,.T.);
#1028=ORIENTED_EDGE('',*,*,#1027,.F.);
#1029=CARTESIAN_POINT('',(147.,3.,0.));
#1030=DIRECTION('',(0.,0.,-1.));
#1031=DIRECTION('',(-1.,0.,0.));
#1032=AXIS2_PLACEMENT_3D('',#1029,#1030,#1031);
#1033=CIRCLE('',#1032,3.);
#1034=CARTESIAN_POINT('',(147.,0.,0.));
#1035=VERTEX_POINT('',#1034);
#1036=EDGE_CURVE('E851',#1026,#1035,#1033,.T.);
#1037=ORIENTED_EDGE('',*,*,#1036,.T.);
#1038=DIRECTION('',(1.,0.,0.));
#1039=VECTOR('',#1038,1.);
#1040=CARTESIAN_POINT('',(0.,0.,0.));
#1041=LINE('',#1040,#1039);
#1042=CARTESIAN_POINT('',(0.,0.,0.));
#1043=VERTEX_POINT('',#1042);
#1044=EDGE_CURVE('E811',#1043,#1035,#1041,.T.);
#1045=ORIENTED_EDGE('',*,*,#1044,.F.);
#1046=DIRECTION('',(0.,-1.,0.));
#1047=VECTOR('',#1046,1.);
#1048=CARTESIAN_POINT('',(0.,0.,0.));
#1049=LINE('',#1048,#1047);
#1050=CARTESIAN_POINT('',(0.,100.,0.));
#1051=VERTEX_POINT('',#1050);
#1052=EDGE_CURVE('E773',#1051,#1043,#1049,.T.);
#1053=ORIENTED_EDGE('',*,*,#1052,.F.);
#1054=DIRECTION('',(-1.,0.,0.));
#1055=VECTOR('',#1054,1.);
#1056=CARTESIAN_POINT('',(0.,100.,0.));
#1057=LINE('',#1056,#1055);
#1058=CARTESIAN_POINT('',(600.,100.,0.));
#1059=VERTEX_POINT('',#1058);
#1060=EDGE_CURVE('E792',#1059,#1051,#1057,.T.);
#1061=ORIENTED_EDGE('',*,*,#1060,.F.);
#1062=DIRECTION('',(0.,1.,0.));
#1063=VECTOR('',#1062,1.);
#1064=CARTESIAN_POINT('',(600.,0.,0.));
#1065=LINE('',#1064,#1063);
#1066=EDGE_CURVE('E824',#975,#1059,#1065,.T.);
#1067=ORIENTED_EDGE('',*,*,#1066,.F.);
#1068=EDGE_LOOP('',(#977,#986,#994,#1003,#1011,#1020,#1028,#1037,#1045,#1053,#1061,#1067));
#1069=FACE_BOUND('',#1068,.T.);
#1070=CARTESIAN_POINT('',(498.5,74.0499999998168,0.));
#1071=DIRECTION('',(0.,0.,1.));
#1072=DIRECTION('',(1.,0.,0.));
#1073=AXIS2_PLACEMENT_3D('',#1070,#1071,#1072);
#1074=CIRCLE('',#1073,2.12132034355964);
#1075=CARTESIAN_POINT('',(497.,72.5499999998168,0.));
#1076=VERTEX_POINT('',#1075);
#1077=CARTESIAN_POINT('',(500.,75.5499999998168,0.));
#1078=VERTEX_POINT('',#1077);
#1079=EDGE_CURVE('E745',#1076,#1078,#1074,.T.);
#1080=ORIENTED_EDGE('',*,*,#1079,.T.);
#1081=DIRECTION('',(0.,-1.,0.));
#1082=VECTOR('',#1081,1.);
#1083=CARTESIAN_POINT('',(500.,0.,0.));
#1084=LINE('',#1083,#1082);
#1085=CARTESIAN_POINT('',(500.,84.6499999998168,0.));
#1086=VERTEX_POINT('',#1085);
#1087=EDGE_CURVE('E725',#1086,#1078,#1084,.T.);
#1088=ORIENTED_EDGE('',*,*,#1087,.F.);
#1089=CARTESIAN_POINT('',(498.5,86.1499999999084,0.));
#1090=DIRECTION('',(0.,0.,1.));
#1091=DIRECTION('',(1.,0.,0.));
#1092=AXIS2_PLACEMENT_3D('',#1089,#1090,#1091);
#1093=CIRCLE('',#1092,2.12132034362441);
#1094=CARTESIAN_POINT('',(497.,87.65,0.));
#1095=VERTEX_POINT('',#1094);
#1096=EDGE_CURVE('E727',#1086,#1095,#1093,.T.);
#1097=ORIENTED_EDGE('',*,*,#1096,.T.);
#1098=DIRECTION('',(-1.,0.,0.));
#1099=VECTOR('',#1098,1.);
#1100=CARTESIAN_POINT('',(0.,87.65,0.));
#1101=LINE('',#1100,#1099);
#1102=CARTESIAN_POINT('',(487.9,87.65,0.));
#1103=VERTEX_POINT('',#1102);
#1104=EDGE_CURVE('E731',#1095,#1103,#1101,.T.);
#1105=ORIENTED_EDGE('',*,*,#1104,.T.);
#1106=CARTESIAN_POINT('',(486.4,86.1499999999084,0.));
#1107=DIRECTION('',(0.,0.,1.));
#1108=DIRECTION('',(1.,0.,0.));
#1109=AXIS2_PLACEMENT_3D('',#1106,#1107,#1108);
#1110=CIRCLE('',#1109,2.12132034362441);
#1111=CARTESIAN_POINT('',(484.9,84.6499999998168,0.));
#1112=VERTEX_POINT('',#1111);
#1113=EDGE_CURVE('E734',#1112,#1103,#1110,.F.);
#1114=ORIENTED_EDGE('',*,*,#1113,.F.);
#1115=DIRECTION('',(0.,-1.,0.));
#1116=VECTOR('',#1115,1.);
#1117=CARTESIAN_POINT('',(484.9,0.,0.));
#1118=LINE('',#1117,#1116);
#1119=CARTESIAN_POINT('',(484.9,75.5499999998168,0.));
#1120=VERTEX_POINT('',#1119);
#1121=EDGE_CURVE('E736',#1112,#1120,#1118,.T.);
#1122=ORIENTED_EDGE('',*,*,#1121,.T.);
#1123=CARTESIAN_POINT('',(486.4,74.0499999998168,0.));
#1124=DIRECTION('',(0.,0.,1.));
#1125=DIRECTION('',(1.,0.,0.));
#1126=AXIS2_PLACEMENT_3D('',#1123,#1124,#1125);
#1127=CIRCLE('',#1126,2.12132034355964);
#1128=CARTESIAN_POINT('',(487.9,72.5499999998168,0.));
#1129=VERTEX_POINT('',#1128);
#1130=EDGE_CURVE('E739',#1120,#1129,#1127,.T.);
#1131=ORIENTED_EDGE('',*,*,#1130,.T.);
#1132=DIRECTION('',(1.,0.,0.));
#1133=VECTOR('',#1132,1.);
#1134=CARTESIAN_POINT('',(0.,72.5499999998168,0.));
#1135=LINE('',#1134,#1133);
#1136=EDGE_CURVE('E742',#1129,#1076,#1135,.T.);
#1137=ORIENTED_EDGE('',*,*,#1136,.T.);
#1138=EDGE_LOOP('',(#1080,#1088,#1097,#1105,#1114,#1122,#1131,#1137));
#1139=FACE_BOUND('',#1138,.T.);
#1140=ADVANCED_FACE('F871',(#606,#676,#746,#816,#827,#897,#967,#1069,#1139),#595,.T.);
#1141=CARTESIAN_POINT('',(0.,0.,15.));
#1142=DIRECTION('',(1.,0.,0.));
#1143=DIRECTION('',(0.,0.,-1.));
#1144=AXIS2_PLACEMENT_3D('',#1141,#1142,#1143);
#1145=PLANE('',#1144);
#1146=ORIENTED_EDGE('',*,*,#1052,.T.);
#1147=DIRECTION('',(0.,0.,-1.));
#1148=VECTOR('',#1147,1.);
#1149=CARTESIAN_POINT('',(0.,0.,15.));
#1150=LINE('',#1149,#1148);
#1151=EDGE_CURVE('E835',#466,#1043,#1150,.T.);
#1152=ORIENTED_EDGE('',*,*,#1151,.F.);
#1153=ORIENTED_EDGE('',*,*,#467,.F.);
#1154=DIRECTION('',(0.,0.,-1.));
#1155=VECTOR('',#1154,1.);
#1156=CARTESIAN_POINT('',(0.,100.,15.));
#1157=LINE('',#1156,#1155);
#1158=EDGE_CURVE('E808',#458,#1051,#1157,.T.);
#1159=ORIENTED_EDGE('',*,*,#1158,.T.);
#1160=EDGE_LOOP('',(#1146,#1152,#1153,#1159));
#1161=FACE_BOUND('',#1160,.T.);
#1162=ADVANCED_FACE('F915',(#1161),#1145,.F.);
#1163=CARTESIAN_POINT('',(0.,0.,15.));
#1164=DIRECTION('',(0.,1.,0.));
#1165=DIRECTION('',(0.,0.,1.));
#1166=AXIS2_PLACEMENT_3D('',#1163,#1164,#1165);
#1167=PLANE('',#1166);
#1168=ORIENTED_EDGE('',*,*,#1044,.T.);
#1169=DIRECTION('',(0.,0.,-1.));
#1170=VECTOR('',#1169,1.);
#1171=CARTESIAN_POINT('',(147.,0.,15.));
#1172=LINE('',#1171,#1170);
#1173=EDGE_CURVE('E862',#1035,#474,#1172,.F.);
#1174=ORIENTED_EDGE('',*,*,#1173,.T.);
#1175=ORIENTED_EDGE('',*,*,#475,.F.);
#1176=ORIENTED_EDGE('',*,*,#1151,.T.);
#1177=EDGE_LOOP('',(#1168,#1174,#1175,#1176));
#1178=FACE_BOUND('',#1177,.T.);
#1179=ADVANCED_FACE('F917',(#1178),#1167,.F.);
#1180=CARTESIAN_POINT('',(150.,0.,15.));
#1181=DIRECTION('',(-1.,0.,0.));
#1182=DIRECTION('',(0.,0.,1.));
#1183=AXIS2_PLACEMENT_3D('',#1180,#1181,#1182);
#1184=PLANE('',#1183);
#1185=ORIENTED_EDGE('',*,*,#1027,.T.);
#1186=DIRECTION('',(0.,0.,-1.));
#1187=VECTOR('',#1186,1.);
#1188=CARTESIAN_POINT('',(150.,13.7043263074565,15.));
#1189=LINE('',#1188,#1187);
#1190=EDGE_CURVE('E50',#1018,#491,#1189,.F.);
#1191=ORIENTED_EDGE('',*,*,#1190,.T.);
#1192=ORIENTED_EDGE('',*,*,#492,.F.);
#1193=DIRECTION('',(0.,0.,-1.));
#1194=VECTOR('',#1193,1.);
#1195=CARTESIAN_POINT('',(150.,3.,15.));
#1196=LINE('',#1195,#1194);
#1197=EDGE_CURVE('E858',#483,#1026,#1196,.T.);
#1198=ORIENTED_EDGE('',*,*,#1197,.T.);
#1199=EDGE_LOOP('',(#1185,#1191,#1192,#1198));
#1200=FACE_BOUND('',#1199,.T.);
#1201=ADVANCED_FACE('F875',(#1200),#1184,.F.);
#1202=CARTESIAN_POINT('',(150.,16.7043263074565,15.));
#1203=DIRECTION('',(0.,1.,0.));
#1204=DIRECTION('',(0.,0.,1.));
#1205=AXIS2_PLACEMENT_3D('',#1202,#1203,#1204);
#1206=PLANE('',#1205);
#1207=ORIENTED_EDGE('',*,*,#1010,.T.);
#1208=DIRECTION('',(0.,0.,-1.));
#1209=VECTOR('',#1208,1.);
#1210=CARTESIAN_POINT('',(447.,16.7043263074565,15.));
#1211=LINE('',#1210,#1209);
#1212=EDGE_CURVE('E846',#1001,#508,#1211,.F.);
#1213=ORIENTED_EDGE('',*,*,#1212,.T.);
#1214=ORIENTED_EDGE('',*,*,#509,.F.);
#1215=DIRECTION('',(0.,0.,-1.));
#1216=VECTOR('',#1215,1.);
#1217=CARTESIAN_POINT('',(153.,16.7043263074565,0.));
#1218=LINE('',#1217,#1216);
#1219=EDGE_CURVE('E843',#500,#1009,#1218,.T.);
#1220=ORIENTED_EDGE('',*,*,#1219,.T.);
#1221=EDGE_LOOP('',(#1207,#1213,#1214,#1220));
#1222=FACE_BOUND('',#1221,.T.);
#1223=ADVANCED_FACE('F883',(#1222),#1206,.F.);
#1224=CARTESIAN_POINT('',(450.,16.7043263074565,15.));
#1225=DIRECTION('',(1.,0.,0.));
#1226=DIRECTION('',(0.,0.,-1.));
#1227=AXIS2_PLACEMENT_3D('',#1224,#1225,#1226);
#1228=PLANE('',#1227);
#1229=ORIENTED_EDGE('',*,*,#426,.F.);
#1230=DIRECTION('',(0.,0.,-1.));
#1231=VECTOR('',#1230,1.);
#1232=CARTESIAN_POINT('',(450.,13.7043263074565,0.));
#1233=LINE('',#1232,#1231);
#1234=EDGE_CURVE('E840',#423,#992,#1233,.T.);
#1235=ORIENTED_EDGE('',*,*,#1234,.T.);
#1236=ORIENTED_EDGE('',*,*,#993,.T.);
#1237=DIRECTION('',(0.,0.,-1.));
#1238=VECTOR('',#1237,1.);
#1239=CARTESIAN_POINT('',(450.,3.,15.));
#1240=LINE('',#1239,#1238);
#1241=EDGE_CURVE('E838',#984,#425,#1240,.F.);
#1242=ORIENTED_EDGE('',*,*,#1241,.T.);
#1243=EDGE_LOOP('',(#1229,#1235,#1236,#1242));
#1244=FACE_BOUND('',#1243,.T.);
#1245=ADVANCED_FACE('F891',(#1244),#1228,.F.);
#1246=CARTESIAN_POINT('',(450.,0.,15.));
#1247=DIRECTION('',(0.,1.,0.));
#1248=DIRECTION('',(0.,0.,1.));
#1249=AXIS2_PLACEMENT_3D('',#1246,#1247,#1248);
#1250=PLANE('',#1249);
#1251=ORIENTED_EDGE('',*,*,#443,.F.);
#1252=DIRECTION('',(0.,0.,-1.));
#1253=VECTOR('',#1252,1.);
#1254=CARTESIAN_POINT('',(453.,0.,15.));
#1255=LINE('',#1254,#1253);
#1256=EDGE_CURVE('E848',#434,#973,#1255,.T.);
#1257=ORIENTED_EDGE('',*,*,#1256,.T.);
#1258=ORIENTED_EDGE('',*,*,#976,.T.);
#1259=DIRECTION('',(0.,0.,-1.));
#1260=VECTOR('',#1259,1.);
#1261=CARTESIAN_POINT('',(600.,0.,15.));
#1262=LINE('',#1261,#1260);
#1263=EDGE_CURVE('E832',#442,#975,#1262,.T.);
#1264=ORIENTED_EDGE('',*,*,#1263,.F.);
#1265=EDGE_LOOP('',(#1251,#1257,#1258,#1264));
#1266=FACE_BOUND('',#1265,.T.);
#1267=ADVANCED_FACE('F900',(#1266),#1250,.F.);
#1268=CARTESIAN_POINT('',(600.,0.,15.));
#1269=DIRECTION('',(-1.,0.,0.));
#1270=DIRECTION('',(0.,0.,1.));
#1271=AXIS2_PLACEMENT_3D('',#1268,#1269,#1270);
#1272=PLANE('',#1271);
#1273=ORIENTED_EDGE('',*,*,#1066,.T.);
#1274=DIRECTION('',(0.,0.,-1.));
#1275=VECTOR('',#1274,1.);
#1276=CARTESIAN_POINT('',(600.,100.,15.));
#1277=LINE('',#1276,#1275);
#1278=EDGE_CURVE('E829',#450,#1059,#1277,.T.);
#1279=ORIENTED_EDGE('',*,*,#1278,.F.);
#1280=ORIENTED_EDGE('',*,*,#451,.F.);
#1281=ORIENTED_EDGE('',*,*,#1263,.T.);
#1282=EDGE_LOOP('',(#1273,#1279,#1280,#1281));
#1283=FACE_BOUND('',#1282,.T.);
#1284=ADVANCED_FACE('F905',(#1283),#1272,.F.);
#1285=CARTESIAN_POINT('',(0.,100.,15.));
#1286=DIRECTION('',(0.,-1.,0.));
#1287=DIRECTION('',(0.,0.,-1.));
#1288=AXIS2_PLACEMENT_3D('',#1285,#1286,#1287);
#1289=PLANE('',#1288);
#1290=ORIENTED_EDGE('',*,*,#1060,.T.);
#1291=ORIENTED_EDGE('',*,*,#1158,.F.);
#1292=ORIENTED_EDGE('',*,*,#459,.F.);
#1293=ORIENTED_EDGE('',*,*,#1278,.T.);
#1294=EDGE_LOOP('',(#1290,#1291,#1292,#1293));
#1295=FACE_BOUND('',#1294,.T.);
#1296=ADVANCED_FACE('F911',(#1295),#1289,.F.);
#1297=CARTESIAN_POINT('',(500.,0.,0.));
#1298=DIRECTION('',(-1.,0.,0.));
#1299=DIRECTION('',(0.,0.,1.));
#1300=AXIS2_PLACEMENT_3D('',#1297,#1298,#1299);
#1301=PLANE('',#1300);
#1302=ORIENTED_EDGE('',*,*,#528,.F.);
#1303=DIRECTION('',(0.,0.,1.));
#1304=VECTOR('',#1303,1.);
#1305=CARTESIAN_POINT('',(500.,84.6499999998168,0.));
#1306=LINE('',#1305,#1304);
#1307=EDGE_CURVE('E748',#1086,#525,#1306,.T.);
#1308=ORIENTED_EDGE('',*,*,#1307,.F.);
#1309=ORIENTED_EDGE('',*,*,#1087,.T.);
#1310=DIRECTION('',(0.,0.,1.));
#1311=VECTOR('',#1310,1.);
#1312=CARTESIAN_POINT('',(500.,75.5499999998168,0.));
#1313=LINE('',#1312,#1311);
#1314=EDGE_CURVE('E771',#1078,#527,#1313,.T.);
#1315=ORIENTED_EDGE('',*,*,#1314,.T.);
#1316=EDGE_LOOP('',(#1302,#1308,#1309,#1315));
#1317=FACE_BOUND('',#1316,.T.);
#1318=ADVANCED_FACE('F936',(#1317),#1301,.T.);
#1319=CARTESIAN_POINT('',(498.5,74.0499999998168,0.));
#1320=DIRECTION('',(0.,0.,1.));
#1321=DIRECTION('',(1.,0.,0.));
#1322=AXIS2_PLACEMENT_3D('',#1319,#1320,#1321);
#1323=CYLINDRICAL_SURFACE('',#1322,2.12132034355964);
#1324=ORIENTED_EDGE('',*,*,#537,.T.);
#1325=ORIENTED_EDGE('',*,*,#1314,.F.);
#1326=ORIENTED_EDGE('',*,*,#1079,.F.);
#1327=DIRECTION('',(0.,0.,1.));
#1328=VECTOR('',#1327,1.);
#1329=CARTESIAN_POINT('',(497.,72.5499999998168,0.));
#1330=LINE('',#1329,#1328);
#1331=EDGE_CURVE('E774',#1076,#536,#1330,.T.);
#1332=ORIENTED_EDGE('',*,*,#1331,.T.);
#1333=EDGE_LOOP('',(#1324,#1325,#1326,#1332));
#1334=FACE_BOUND('',#1333,.T.);
#1335=ADVANCED_FACE('F1440',(#1334),#1323,.F.);
#1336=CARTESIAN_POINT('',(0.,72.5499999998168,0.));
#1337=DIRECTION('',(0.,-1.,0.));
#1338=DIRECTION('',(0.,0.,-1.));
#1339=AXIS2_PLACEMENT_3D('',#1336,#1337,#1338);
#1340=PLANE('',#1339);
#1341=ORIENTED_EDGE('',*,*,#545,.T.);
#1342=ORIENTED_EDGE('',*,*,#1331,.F.);
#1343=ORIENTED_EDGE('',*,*,#1136,.F.);
#1344=DIRECTION('',(0.,0.,1.));
#1345=VECTOR('',#1344,1.);
#1346=CARTESIAN_POINT('',(487.9,72.5499999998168,0.));
#1347=LINE('',#1346,#1345);
#1348=EDGE_CURVE('E776',#1129,#544,#1347,.T.);
#1349=ORIENTED_EDGE('',*,*,#1348,.T.);
#1350=EDGE_LOOP('',(#1341,#1342,#1343,#1349));
#1351=FACE_BOUND('',#1350,.T.);
#1352=ADVANCED_FACE('F1431',(#1351),#1340,.F.);
#1353=CARTESIAN_POINT('',(486.4,74.0499999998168,0.));
#1354=DIRECTION('',(0.,0.,1.));
#1355=DIRECTION('',(1.,0.,0.));
#1356=AXIS2_PLACEMENT_3D('',#1353,#1354,#1355);
#1357=CYLINDRICAL_SURFACE('',#1356,2.12132034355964);
#1358=ORIENTED_EDGE('',*,*,#554,.T.);
#1359=ORIENTED_EDGE('',*,*,#1348,.F.);
#1360=ORIENTED_EDGE('',*,*,#1130,.F.);
#1361=DIRECTION('',(0.,0.,1.));
#1362=VECTOR('',#1361,1.);
#1363=CARTESIAN_POINT('',(484.9,75.5499999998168,0.));
#1364=LINE('',#1363,#1362);
#1365=EDGE_CURVE('E778',#1120,#553,#1364,.T.);
#1366=ORIENTED_EDGE('',*,*,#1365,.T.);
#1367=EDGE_LOOP('',(#1358,#1359,#1360,#1366));
#1368=FACE_BOUND('',#1367,.T.);
#1369=ADVANCED_FACE('F1422',(#1368),#1357,.F.);
#1370=CARTESIAN_POINT('',(484.9,0.,0.));
#1371=DIRECTION('',(-1.,0.,0.));
#1372=DIRECTION('',(0.,0.,1.));
#1373=AXIS2_PLACEMENT_3D('',#1370,#1371,#1372);
#1374=PLANE('',#1373);
#1375=ORIENTED_EDGE('',*,*,#562,.T.);
#1376=ORIENTED_EDGE('',*,*,#1365,.F.);
#1377=ORIENTED_EDGE('',*,*,#1121,.F.);
#1378=DIRECTION('',(0.,0.,1.));
#1379=VECTOR('',#1378,1.);
#1380=CARTESIAN_POINT('',(484.9,84.6499999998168,0.));
#1381=LINE('',#1380,#1379);
#1382=EDGE_CURVE('E780',#1112,#561,#1381,.T.);
#1383=ORIENTED_EDGE('',*,*,#1382,.T.);
#1384=EDGE_LOOP('',(#1375,#1376,#1377,#1383));
#1385=FACE_BOUND('',#1384,.T.);
#1386=ADVANCED_FACE('F1413',(#1385),#1374,.F.);
#1387=CARTESIAN_POINT('',(486.4,86.1499999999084,0.));
#1388=DIRECTION('',(0.,0.,1.));
#1389=DIRECTION('',(1.,0.,0.));
#1390=AXIS2_PLACEMENT_3D('',#1387,#1388,#1389);
#1391=CYLINDRICAL_SURFACE('',#1390,2.12132034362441);
#1392=ORIENTED_EDGE('',*,*,#571,.F.);
#1393=ORIENTED_EDGE('',*,*,#1382,.F.);
#1394=ORIENTED_EDGE('',*,*,#1113,.T.);
#1395=DIRECTION('',(0.,0.,1.));
#1396=VECTOR('',#1395,1.);
#1397=CARTESIAN_POINT('',(487.9,87.65,0.));
#1398=LINE('',#1397,#1396);
#1399=EDGE_CURVE('E782',#1103,#570,#1398,.T.);
#1400=ORIENTED_EDGE('',*,*,#1399,.T.);
#1401=EDGE_LOOP('',(#1392,#1393,#1394,#1400));
#1402=FACE_BOUND('',#1401,.T.);
#1403=ADVANCED_FACE('F1404',(#1402),#1391,.F.);
#1404=CARTESIAN_POINT('',(0.,87.65,0.));
#1405=DIRECTION('',(0.,1.,0.));
#1406=DIRECTION('',(0.,0.,1.));
#1407=AXIS2_PLACEMENT_3D('',#1404,#1405,#1406);
#1408=PLANE('',#1407);
#1409=ORIENTED_EDGE('',*,*,#579,.T.);
#1410=ORIENTED_EDGE('',*,*,#1399,.F.);
#1411=ORIENTED_EDGE('',*,*,#1104,.F.);
#1412=DIRECTION('',(0.,0.,1.));
#1413=VECTOR('',#1412,1.);
#1414=CARTESIAN_POINT('',(497.,87.65,0.));
#1415=LINE('',#1414,#1413);
#1416=EDGE_CURVE('E784',#1095,#578,#1415,.T.);
#1417=ORIENTED_EDGE('',*,*,#1416,.T.);
#1418=EDGE_LOOP('',(#1409,#1410,#1411,#1417));
#1419=FACE_BOUND('',#1418,.T.);
#1420=ADVANCED_FACE('F1396',(#1419),#1408,.F.);
#1421=CARTESIAN_POINT('',(498.5,86.1499999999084,0.));
#1422=DIRECTION('',(0.,0.,1.));
#1423=DIRECTION('',(1.,0.,0.));
#1424=AXIS2_PLACEMENT_3D('',#1421,#1422,#1423);
#1425=CYLINDRICAL_SURFACE('',#1424,2.12132034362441);
#1426=ORIENTED_EDGE('',*,*,#586,.T.);
#1427=ORIENTED_EDGE('',*,*,#1416,.F.);
#1428=ORIENTED_EDGE('',*,*,#1096,.F.);
#1429=ORIENTED_EDGE('',*,*,#1307,.T.);
#1430=EDGE_LOOP('',(#1426,#1427,#1428,#1429));
#1431=FACE_BOUND('',#1430,.T.);
#1432=ADVANCED_FACE('F1387',(#1431),#1425,.F.);
#1433=CARTESIAN_POINT('',(500.,0.,0.));
#1434=DIRECTION('',(1.,0.,0.));
#1435=DIRECTION('',(0.,0.,-1.));
#1436=AXIS2_PLACEMENT_3D('',#1433,#1434,#1435);
#1437=PLANE('',#1436);
#1438=ORIENTED_EDGE('',*,*,#365,.T.);
#1439=DIRECTION('',(0.,0.,1.));
#1440=VECTOR('',#1439,1.);
#1441=CARTESIAN_POINT('',(500.,24.4499999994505,0.));
#1442=LINE('',#1441,#1440);
#1443=EDGE_CURVE('E662',#905,#354,#1442,.T.);
#1444=ORIENTED_EDGE('',*,*,#1443,.F.);
#1445=ORIENTED_EDGE('',*,*,#906,.F.);
#1446=DIRECTION('',(0.,0.,1.));
#1447=VECTOR('',#1446,1.);
#1448=CARTESIAN_POINT('',(500.,15.3499999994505,0.));
#1449=LINE('',#1448,#1447);
#1450=EDGE_CURVE('E640',#903,#364,#1449,.T.);
#1451=ORIENTED_EDGE('',*,*,#1450,.T.);
#1452=EDGE_LOOP('',(#1438,#1444,#1445,#1451));
#1453=FACE_BOUND('',#1452,.T.);
#1454=ADVANCED_FACE('F1378',(#1453),#1437,.F.);
#1455=CARTESIAN_POINT('',(498.5,13.8499999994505,0.));
#1456=DIRECTION('',(0.,0.,1.));
#1457=DIRECTION('',(1.,0.,0.));
#1458=AXIS2_PLACEMENT_3D('',#1455,#1456,#1457);
#1459=CYLINDRICAL_SURFACE('',#1458,2.12132034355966);
#1460=ORIENTED_EDGE('',*,*,#374,.T.);
#1461=ORIENTED_EDGE('',*,*,#1450,.F.);
#1462=ORIENTED_EDGE('',*,*,#964,.F.);
#1463=DIRECTION('',(0.,0.,1.));
#1464=VECTOR('',#1463,1.);
#1465=CARTESIAN_POINT('',(497.,12.3499999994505,0.));
#1466=LINE('',#1465,#1464);
#1467=EDGE_CURVE('E676',#956,#373,#1466,.T.);
#1468=ORIENTED_EDGE('',*,*,#1467,.T.);
#1469=EDGE_LOOP('',(#1460,#1461,#1462,#1468));
#1470=FACE_BOUND('',#1469,.T.);
#1471=ADVANCED_FACE('F1369',(#1470),#1459,.F.);
#1472=CARTESIAN_POINT('',(0.,12.3499999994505,0.));
#1473=DIRECTION('',(0.,-1.,0.));
#1474=DIRECTION('',(0.,0.,-1.));
#1475=AXIS2_PLACEMENT_3D('',#1472,#1473,#1474);
#1476=PLANE('',#1475);
#1477=ORIENTED_EDGE('',*,*,#382,.T.);
#1478=ORIENTED_EDGE('',*,*,#1467,.F.);
#1479=ORIENTED_EDGE('',*,*,#957,.F.);
#1480=DIRECTION('',(0.,0.,1.));
#1481=VECTOR('',#1480,1.);
#1482=CARTESIAN_POINT('',(487.9,12.3499999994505,0.));
#1483=LINE('',#1482,#1481);
#1484=EDGE_CURVE('E674',#948,#381,#1483,.T.);
#1485=ORIENTED_EDGE('',*,*,#1484,.T.);
#1486=EDGE_LOOP('',(#1477,#1478,#1479,#1485));
#1487=FACE_BOUND('',#1486,.T.);
#1488=ADVANCED_FACE('F1360',(#1487),#1476,.F.);
#1489=CARTESIAN_POINT('',(486.4,13.8499999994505,0.));
#1490=DIRECTION('',(0.,0.,1.));
#1491=DIRECTION('',(1.,0.,0.));
#1492=AXIS2_PLACEMENT_3D('',#1489,#1490,#1491);
#1493=CYLINDRICAL_SURFACE('',#1492,2.12132034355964);
#1494=ORIENTED_EDGE('',*,*,#391,.T.);
#1495=ORIENTED_EDGE('',*,*,#1484,.F.);
#1496=ORIENTED_EDGE('',*,*,#949,.F.);
#1497=DIRECTION('',(0.,0.,1.));
#1498=VECTOR('',#1497,1.);
#1499=CARTESIAN_POINT('',(484.9,15.3499999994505,0.));
#1500=LINE('',#1499,#1498);
#1501=EDGE_CURVE('E672',#939,#390,#1500,.T.);
#1502=ORIENTED_EDGE('',*,*,#1501,.T.);
#1503=EDGE_LOOP('',(#1494,#1495,#1496,#1502));
#1504=FACE_BOUND('',#1503,.T.);
#1505=ADVANCED_FACE('F1351',(#1504),#1493,.F.);
#1506=CARTESIAN_POINT('',(484.9,0.,0.));
#1507=DIRECTION('',(-1.,0.,0.));
#1508=DIRECTION('',(0.,0.,1.));
#1509=AXIS2_PLACEMENT_3D('',#1506,#1507,#1508);
#1510=PLANE('',#1509);
#1511=ORIENTED_EDGE('',*,*,#399,.T.);
#1512=ORIENTED_EDGE('',*,*,#1501,.F.);
#1513=ORIENTED_EDGE('',*,*,#940,.F.);
#1514=DIRECTION('',(0.,0.,1.));
#1515=VECTOR('',#1514,1.);
#1516=CARTESIAN_POINT('',(484.9,24.4499999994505,0.));
#1517=LINE('',#1516,#1515);
#1518=EDGE_CURVE('E670',#931,#398,#1517,.T.);
#1519=ORIENTED_EDGE('',*,*,#1518,.T.);
#1520=EDGE_LOOP('',(#1511,#1512,#1513,#1519));
#1521=FACE_BOUND('',#1520,.T.);
#1522=ADVANCED_FACE('F1342',(#1521),#1510,.F.);
#1523=CARTESIAN_POINT('',(486.4,25.9499999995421,0.));
#1524=DIRECTION('',(0.,0.,1.));
#1525=DIRECTION('',(1.,0.,0.));
#1526=AXIS2_PLACEMENT_3D('',#1523,#1524,#1525);
#1527=CYLINDRICAL_SURFACE('',#1526,2.12132034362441);
#1528=ORIENTED_EDGE('',*,*,#408,.F.);
#1529=ORIENTED_EDGE('',*,*,#1518,.F.);
#1530=ORIENTED_EDGE('',*,*,#932,.T.);
#1531=DIRECTION('',(0.,0.,1.));
#1532=VECTOR('',#1531,1.);
#1533=CARTESIAN_POINT('',(487.9,27.4499999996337,0.));
#1534=LINE('',#1533,#1532);
#1535=EDGE_CURVE('E668',#922,#407,#1534,.T.);
#1536=ORIENTED_EDGE('',*,*,#1535,.T.);
#1537=EDGE_LOOP('',(#1528,#1529,#1530,#1536));
#1538=FACE_BOUND('',#1537,.T.);
#1539=ADVANCED_FACE('F1333',(#1538),#1527,.F.);
#1540=CARTESIAN_POINT('',(0.,27.4499999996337,0.));
#1541=DIRECTION('',(0.,1.,0.));
#1542=DIRECTION('',(0.,0.,1.));
#1543=AXIS2_PLACEMENT_3D('',#1540,#1541,#1542);
#1544=PLANE('',#1543);
#1545=ORIENTED_EDGE('',*,*,#414,.T.);
#1546=ORIENTED_EDGE('',*,*,#1535,.F.);
#1547=ORIENTED_EDGE('',*,*,#923,.F.);
#1548=DIRECTION('',(0.,0.,1.));
#1549=VECTOR('',#1548,1.);
#1550=CARTESIAN_POINT('',(497.,27.4499999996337,0.));
#1551=LINE('',#1550,#1549);
#1552=EDGE_CURVE('E666',#914,#356,#1551,.T.);
#1553=ORIENTED_EDGE('',*,*,#1552,.T.);
#1554=EDGE_LOOP('',(#1545,#1546,#1547,#1553));
#1555=FACE_BOUND('',#1554,.T.);
#1556=ADVANCED_FACE('F1324',(#1555),#1544,.F.);
#1557=CARTESIAN_POINT('',(498.5,25.9499999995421,0.));
#1558=DIRECTION('',(0.,0.,1.));
#1559=DIRECTION('',(1.,0.,0.));
#1560=AXIS2_PLACEMENT_3D('',#1557,#1558,#1559);
#1561=CYLINDRICAL_SURFACE('',#1560,2.12132034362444);
#1562=ORIENTED_EDGE('',*,*,#357,.T.);
#1563=ORIENTED_EDGE('',*,*,#1552,.F.);
#1564=ORIENTED_EDGE('',*,*,#915,.F.);
#1565=ORIENTED_EDGE('',*,*,#1443,.T.);
#1566=EDGE_LOOP('',(#1562,#1563,#1564,#1565));
#1567=FACE_BOUND('',#1566,.T.);
#1568=ADVANCED_FACE('F1315',(#1567),#1561,.F.);
#1569=CARTESIAN_POINT('',(500.,0.,0.));
#1570=DIRECTION('',(1.,0.,0.));
#1571=DIRECTION('',(0.,0.,-1.));
#1572=AXIS2_PLACEMENT_3D('',#1569,#1570,#1571);
#1573=PLANE('',#1572);
#1574=ORIENTED_EDGE('',*,*,#295,.T.);
#1575=DIRECTION('',(0.,0.,1.));
#1576=VECTOR('',#1575,1.);
#1577=CARTESIAN_POINT('',(500.,54.5499999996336,0.));
#1578=LINE('',#1577,#1576);
#1579=EDGE_CURVE('E599',#835,#284,#1578,.T.);
#1580=ORIENTED_EDGE('',*,*,#1579,.F.);
#1581=ORIENTED_EDGE('',*,*,#836,.F.);
#1582=DIRECTION('',(0.,0.,1.));
#1583=VECTOR('',#1582,1.);
#1584=CARTESIAN_POINT('',(500.,45.4499999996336,0.));
#1585=LINE('',#1584,#1583);
#1586=EDGE_CURVE('E596',#833,#294,#1585,.T.);
#1587=ORIENTED_EDGE('',*,*,#1586,.T.);
#1588=EDGE_LOOP('',(#1574,#1580,#1581,#1587));
#1589=FACE_BOUND('',#1588,.T.);
#1590=ADVANCED_FACE('F1306',(#1589),#1573,.F.);
#1591=CARTESIAN_POINT('',(498.5,43.9499999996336,0.));
#1592=DIRECTION('',(0.,0.,1.));
#1593=DIRECTION('',(1.,0.,0.));
#1594=AXIS2_PLACEMENT_3D('',#1591,#1592,#1593);
#1595=CYLINDRICAL_SURFACE('',#1594,2.12132034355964);
#1596=ORIENTED_EDGE('',*,*,#304,.T.);
#1597=ORIENTED_EDGE('',*,*,#1586,.F.);
#1598=ORIENTED_EDGE('',*,*,#894,.F.);
#1599=DIRECTION('',(0.,0.,1.));
#1600=VECTOR('',#1599,1.);
#1601=CARTESIAN_POINT('',(497.,42.4499999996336,0.));
#1602=LINE('',#1601,#1600);
#1603=EDGE_CURVE('E613',#886,#303,#1602,.T.);
#1604=ORIENTED_EDGE('',*,*,#1603,.T.);
#1605=EDGE_LOOP('',(#1596,#1597,#1598,#1604));
#1606=FACE_BOUND('',#1605,.T.);
#1607=ADVANCED_FACE('F1297',(#1606),#1595,.F.);
#1608=CARTESIAN_POINT('',(0.,42.4499999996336,0.));
#1609=DIRECTION('',(0.,-1.,0.));
#1610=DIRECTION('',(0.,0.,-1.));
#1611=AXIS2_PLACEMENT_3D('',#1608,#1609,#1610);
#1612=PLANE('',#1611);
#1613=ORIENTED_EDGE('',*,*,#312,.T.);
#1614=ORIENTED_EDGE('',*,*,#1603,.F.);
#1615=ORIENTED_EDGE('',*,*,#887,.F.);
#1616=DIRECTION('',(0.,0.,1.));
#1617=VECTOR('',#1616,1.);
#1618=CARTESIAN_POINT('',(487.9,42.4499999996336,0.));
#1619=LINE('',#1618,#1617);
#1620=EDGE_CURVE('E611',#878,#311,#1619,.T.);
#1621=ORIENTED_EDGE('',*,*,#1620,.T.);
#1622=EDGE_LOOP('',(#1613,#1614,#1615,#1621));
#1623=FACE_BOUND('',#1622,.T.);
#1624=ADVANCED_FACE('F1288',(#1623),#1612,.F.);
#1625=CARTESIAN_POINT('',(486.4,43.9499999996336,0.));
#1626=DIRECTION('',(0.,0.,1.));
#1627=DIRECTION('',(1.,0.,0.));
#1628=AXIS2_PLACEMENT_3D('',#1625,#1626,#1627);
#1629=CYLINDRICAL_SURFACE('',#1628,2.12132034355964);
#1630=ORIENTED_EDGE('',*,*,#321,.T.);
#1631=ORIENTED_EDGE('',*,*,#1620,.F.);
#1632=ORIENTED_EDGE('',*,*,#879,.F.);
#1633=DIRECTION('',(0.,0.,1.));
#1634=VECTOR('',#1633,1.);
#1635=CARTESIAN_POINT('',(484.9,45.4499999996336,0.));
#1636=LINE('',#1635,#1634);
#1637=EDGE_CURVE('E609',#869,#320,#1636,.T.);
#1638=ORIENTED_EDGE('',*,*,#1637,.T.);
#1639=EDGE_LOOP('',(#1630,#1631,#1632,#1638));
#1640=FACE_BOUND('',#1639,.T.);
#1641=ADVANCED_FACE('F1279',(#1640),#1629,.F.);
#1642=CARTESIAN_POINT('',(484.9,0.,0.));
#1643=DIRECTION('',(-1.,0.,0.));
#1644=DIRECTION('',(0.,0.,1.));
#1645=AXIS2_PLACEMENT_3D('',#1642,#1643,#1644);
#1646=PLANE('',#1645);
#1647=ORIENTED_EDGE('',*,*,#329,.T.);
#1648=ORIENTED_EDGE('',*,*,#1637,.F.);
#1649=ORIENTED_EDGE('',*,*,#870,.F.);
#1650=DIRECTION('',(0.,0.,1.));
#1651=VECTOR('',#1650,1.);
#1652=CARTESIAN_POINT('',(484.9,54.5499999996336,0.));
#1653=LINE('',#1652,#1651);
#1654=EDGE_CURVE('E607',#861,#328,#1653,.T.);
#1655=ORIENTED_EDGE('',*,*,#1654,.T.);
#1656=EDGE_LOOP('',(#1647,#1648,#1649,#1655));
#1657=FACE_BOUND('',#1656,.T.);
#1658=ADVANCED_FACE('F1270',(#1657),#1646,.F.);
#1659=CARTESIAN_POINT('',(486.4,56.0499999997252,0.));
#1660=DIRECTION('',(0.,0.,1.));
#1661=DIRECTION('',(1.,0.,0.));
#1662=AXIS2_PLACEMENT_3D('',#1659,#1660,#1661);
#1663=CYLINDRICAL_SURFACE('',#1662,2.12132034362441);
#1664=ORIENTED_EDGE('',*,*,#338,.F.);
#1665=ORIENTED_EDGE('',*,*,#1654,.F.);
#1666=ORIENTED_EDGE('',*,*,#862,.T.);
#1667=DIRECTION('',(0.,0.,1.));
#1668=VECTOR('',#1667,1.);
#1669=CARTESIAN_POINT('',(487.9,57.5499999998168,0.));
#1670=LINE('',#1669,#1668);
#1671=EDGE_CURVE('E605',#852,#337,#1670,.T.);
#1672=ORIENTED_EDGE('',*,*,#1671,.T.);
#1673=EDGE_LOOP('',(#1664,#1665,#1666,#1672));
#1674=FACE_BOUND('',#1673,.T.);
#1675=ADVANCED_FACE('F1261',(#1674),#1663,.F.);
#1676=CARTESIAN_POINT('',(0.,57.5499999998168,0.));
#1677=DIRECTION('',(0.,1.,0.));
#1678=DIRECTION('',(0.,0.,1.));
#1679=AXIS2_PLACEMENT_3D('',#1676,#1677,#1678);
#1680=PLANE('',#1679);
#1681=ORIENTED_EDGE('',*,*,#344,.T.);
#1682=ORIENTED_EDGE('',*,*,#1671,.F.);
#1683=ORIENTED_EDGE('',*,*,#853,.F.);
#1684=DIRECTION('',(0.,0.,1.));
#1685=VECTOR('',#1684,1.);
#1686=CARTESIAN_POINT('',(497.,57.5499999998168,0.));
#1687=LINE('',#1686,#1685);
#1688=EDGE_CURVE('E603',#844,#286,#1687,.T.);
#1689=ORIENTED_EDGE('',*,*,#1688,.T.);
#1690=EDGE_LOOP('',(#1681,#1682,#1683,#1689));
#1691=FACE_BOUND('',#1690,.T.);
#1692=ADVANCED_FACE('F1252',(#1691),#1680,.F.);
#1693=CARTESIAN_POINT('',(498.5,56.0499999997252,0.));
#1694=DIRECTION('',(0.,0.,1.));
#1695=DIRECTION('',(1.,0.,0.));
#1696=AXIS2_PLACEMENT_3D('',#1693,#1694,#1695);
#1697=CYLINDRICAL_SURFACE('',#1696,2.12132034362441);
#1698=ORIENTED_EDGE('',*,*,#287,.T.);
#1699=ORIENTED_EDGE('',*,*,#1688,.F.);
#1700=ORIENTED_EDGE('',*,*,#845,.F.);
#1701=ORIENTED_EDGE('',*,*,#1579,.T.);
#1702=EDGE_LOOP('',(#1698,#1699,#1700,#1701));
#1703=FACE_BOUND('',#1702,.T.);
#1704=ADVANCED_FACE('F1243',(#1703),#1697,.F.);
#1705=CARTESIAN_POINT('',(45.5,69.5,0.));
#1706=DIRECTION('',(0.,0.,1.));
#1707=DIRECTION('',(1.,0.,0.));
#1708=AXIS2_PLACEMENT_3D('',#1705,#1706,#1707);
#1709=CYLINDRICAL_SURFACE('',#1708,3.525);
#1710=ORIENTED_EDGE('',*,*,#824,.F.);
#1711=EDGE_LOOP('',(#1710));
#1712=FACE_BOUND('',#1711,.T.);
#1713=ORIENTED_EDGE('',*,*,#274,.T.);
#1714=EDGE_LOOP('',(#1713));
#1715=FACE_BOUND('',#1714,.T.);
#1716=ADVANCED_FACE('F1234',(#1712,#1715),#1709,.F.);
#1717=CARTESIAN_POINT('',(101.5,74.0500000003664,0.));
#1718=DIRECTION('',(0.,0.,1.));
#1719=DIRECTION('',(1.,0.,0.));
#1720=AXIS2_PLACEMENT_3D('',#1717,#1718,#1719);
#1721=CYLINDRICAL_SURFACE('',#1720,2.12132034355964);
#1722=ORIENTED_EDGE('',*,*,#214,.T.);
#1723=DIRECTION('',(0.,0.,1.));
#1724=VECTOR('',#1723,1.);
#1725=CARTESIAN_POINT('',(103.,72.5500000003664,0.));
#1726=LINE('',#1725,#1724);
#1727=EDGE_CURVE('E530',#755,#202,#1726,.T.);
#1728=ORIENTED_EDGE('',*,*,#1727,.F.);
#1729=ORIENTED_EDGE('',*,*,#756,.F.);
#1730=DIRECTION('',(0.,0.,1.));
#1731=VECTOR('',#1730,1.);
#1732=CARTESIAN_POINT('',(100.,75.5500000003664,0.));
#1733=LINE('',#1732,#1731);
#1734=EDGE_CURVE('E508',#753,#213,#1733,.T.);
#1735=ORIENTED_EDGE('',*,*,#1734,.T.);
#1736=EDGE_LOOP('',(#1722,#1728,#1729,#1735));
#1737=FACE_BOUND('',#1736,.T.);
#1738=ADVANCED_FACE('F1225',(#1737),#1721,.F.);
#1739=CARTESIAN_POINT('',(100.,84.6500000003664,0.));
#1740=DIRECTION('',(-1.,0.,0.));
#1741=DIRECTION('',(0.,-1.,0.));
#1742=AXIS2_PLACEMENT_3D('',#1739,#1740,#1741);
#1743=PLANE('',#1742);
#1744=ORIENTED_EDGE('',*,*,#222,.T.);
#1745=ORIENTED_EDGE('',*,*,#1734,.F.);
#1746=ORIENTED_EDGE('',*,*,#813,.F.);
#1747=DIRECTION('',(0.,0.,1.));
#1748=VECTOR('',#1747,1.);
#1749=CARTESIAN_POINT('',(100.,84.6500000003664,0.));
#1750=LINE('',#1749,#1748);
#1751=EDGE_CURVE('E544',#806,#221,#1750,.T.);
#1752=ORIENTED_EDGE('',*,*,#1751,.T.);
#1753=EDGE_LOOP('',(#1744,#1745,#1746,#1752));
#1754=FACE_BOUND('',#1753,.T.);
#1755=ADVANCED_FACE('F1216',(#1754),#1743,.F.);
#1756=CARTESIAN_POINT('',(101.5,86.150000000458,0.));
#1757=DIRECTION('',(0.,0.,1.));
#1758=DIRECTION('',(1.,0.,0.));
#1759=AXIS2_PLACEMENT_3D('',#1756,#1757,#1758);
#1760=CYLINDRICAL_SURFACE('',#1759,2.12132034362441);
#1761=ORIENTED_EDGE('',*,*,#231,.F.);
#1762=ORIENTED_EDGE('',*,*,#1751,.F.);
#1763=ORIENTED_EDGE('',*,*,#807,.T.);
#1764=DIRECTION('',(0.,0.,1.));
#1765=VECTOR('',#1764,1.);
#1766=CARTESIAN_POINT('',(103.,87.6500000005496,0.));
#1767=LINE('',#1766,#1765);
#1768=EDGE_CURVE('E542',#797,#230,#1767,.T.);
#1769=ORIENTED_EDGE('',*,*,#1768,.T.);
#1770=EDGE_LOOP('',(#1761,#1762,#1763,#1769));
#1771=FACE_BOUND('',#1770,.T.);
#1772=ADVANCED_FACE('F1207',(#1771),#1760,.F.);
#1773=CARTESIAN_POINT('',(112.1,87.6500000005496,0.));
#1774=DIRECTION('',(0.,1.,0.));
#1775=DIRECTION('',(-1.,0.,0.));
#1776=AXIS2_PLACEMENT_3D('',#1773,#1774,#1775);
#1777=PLANE('',#1776);
#1778=ORIENTED_EDGE('',*,*,#239,.T.);
#1779=ORIENTED_EDGE('',*,*,#1768,.F.);
#1780=ORIENTED_EDGE('',*,*,#798,.F.);
#1781=DIRECTION('',(0.,0.,1.));
#1782=VECTOR('',#1781,1.);
#1783=CARTESIAN_POINT('',(112.1,87.6500000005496,0.));
#1784=LINE('',#1783,#1782);
#1785=EDGE_CURVE('E540',#789,#238,#1784,.T.);
#1786=ORIENTED_EDGE('',*,*,#1785,.T.);
#1787=EDGE_LOOP('',(#1778,#1779,#1780,#1786));
#1788=FACE_BOUND('',#1787,.T.);
#1789=ADVANCED_FACE('F1198',(#1788),#1777,.F.);
#1790=CARTESIAN_POINT('',(113.6,86.150000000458,0.));
#1791=DIRECTION('',(0.,0.,1.));
#1792=DIRECTION('',(1.,0.,0.));
#1793=AXIS2_PLACEMENT_3D('',#1790,#1791,#1792);
#1794=CYLINDRICAL_SURFACE('',#1793,2.12132034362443);
#1795=ORIENTED_EDGE('',*,*,#248,.T.);
#1796=ORIENTED_EDGE('',*,*,#1785,.F.);
#1797=ORIENTED_EDGE('',*,*,#790,.F.);
#1798=DIRECTION('',(0.,0.,1.));
#1799=VECTOR('',#1798,1.);
#1800=CARTESIAN_POINT('',(115.1,84.6500000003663,0.));
#1801=LINE('',#1800,#1799);
#1802=EDGE_CURVE('E538',#780,#247,#1801,.T.);
#1803=ORIENTED_EDGE('',*,*,#1802,.T.);
#1804=EDGE_LOOP('',(#1795,#1796,#1797,#1803));
#1805=FACE_BOUND('',#1804,.T.);
#1806=ADVANCED_FACE('F1189',(#1805),#1794,.F.);
#1807=CARTESIAN_POINT('',(115.1,75.5500000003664,0.));
#1808=DIRECTION('',(1.,0.,0.));
#1809=DIRECTION('',(0.,0.,-1.));
#1810=AXIS2_PLACEMENT_3D('',#1807,#1808,#1809);
#1811=PLANE('',#1810);
#1812=ORIENTED_EDGE('',*,*,#256,.T.);
#1813=ORIENTED_EDGE('',*,*,#1802,.F.);
#1814=ORIENTED_EDGE('',*,*,#781,.F.);
#1815=DIRECTION('',(0.,0.,1.));
#1816=VECTOR('',#1815,1.);
#1817=CARTESIAN_POINT('',(115.1,75.5500000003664,0.));
#1818=LINE('',#1817,#1816);
#1819=EDGE_CURVE('E536',#772,#255,#1818,.T.);
#1820=ORIENTED_EDGE('',*,*,#1819,.T.);
#1821=EDGE_LOOP('',(#1812,#1813,#1814,#1820));
#1822=FACE_BOUND('',#1821,.T.);
#1823=ADVANCED_FACE('F1180',(#1822),#1811,.F.);
#1824=CARTESIAN_POINT('',(113.6,74.0500000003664,0.));
#1825=DIRECTION('',(0.,0.,1.));
#1826=DIRECTION('',(1.,0.,0.));
#1827=AXIS2_PLACEMENT_3D('',#1824,#1825,#1826);
#1828=CYLINDRICAL_SURFACE('',#1827,2.12132034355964);
#1829=ORIENTED_EDGE('',*,*,#263,.T.);
#1830=ORIENTED_EDGE('',*,*,#1819,.F.);
#1831=ORIENTED_EDGE('',*,*,#773,.F.);
#1832=DIRECTION('',(0.,0.,1.));
#1833=VECTOR('',#1832,1.);
#1834=CARTESIAN_POINT('',(112.1,72.5500000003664,0.));
#1835=LINE('',#1834,#1833);
#1836=EDGE_CURVE('E534',#763,#204,#1835,.T.);
#1837=ORIENTED_EDGE('',*,*,#1836,.T.);
#1838=EDGE_LOOP('',(#1829,#1830,#1831,#1837));
#1839=FACE_BOUND('',#1838,.T.);
#1840=ADVANCED_FACE('F1171',(#1839),#1828,.F.);
#1841=CARTESIAN_POINT('',(103.,72.5500000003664,0.));
#1842=DIRECTION('',(0.,-1.,0.));
#1843=DIRECTION('',(1.,0.,0.));
#1844=AXIS2_PLACEMENT_3D('',#1841,#1842,#1843);
#1845=PLANE('',#1844);
#1846=ORIENTED_EDGE('',*,*,#205,.T.);
#1847=ORIENTED_EDGE('',*,*,#1836,.F.);
#1848=ORIENTED_EDGE('',*,*,#764,.F.);
#1849=ORIENTED_EDGE('',*,*,#1727,.T.);
#1850=EDGE_LOOP('',(#1846,#1847,#1848,#1849));
#1851=FACE_BOUND('',#1850,.T.);
#1852=ADVANCED_FACE('F1162',(#1851),#1845,.F.);
#1853=CARTESIAN_POINT('',(103.,42.4500000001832,0.));
#1854=DIRECTION('',(0.,-1.,0.));
#1855=DIRECTION('',(0.,0.,-1.));
#1856=AXIS2_PLACEMENT_3D('',#1853,#1854,#1855);
#1857=PLANE('',#1856);
#1858=ORIENTED_EDGE('',*,*,#144,.T.);
#1859=DIRECTION('',(0.,0.,1.));
#1860=VECTOR('',#1859,1.);
#1861=CARTESIAN_POINT('',(112.1,42.4500000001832,0.));
#1862=LINE('',#1861,#1860);
#1863=EDGE_CURVE('E469',#684,#133,#1862,.T.);
#1864=ORIENTED_EDGE('',*,*,#1863,.F.);
#1865=ORIENTED_EDGE('',*,*,#685,.F.);
#1866=DIRECTION('',(0.,0.,1.));
#1867=VECTOR('',#1866,1.);
#1868=CARTESIAN_POINT('',(103.,42.4500000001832,0.));
#1869=LINE('',#1868,#1867);
#1870=EDGE_CURVE('E439',#682,#143,#1869,.T.);
#1871=ORIENTED_EDGE('',*,*,#1870,.T.);
#1872=EDGE_LOOP('',(#1858,#1864,#1865,#1871));
#1873=FACE_BOUND('',#1872,.T.);
#1874=ADVANCED_FACE('F1153',(#1873),#1857,.F.);
#1875=CARTESIAN_POINT('',(101.5,43.9500000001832,0.));
#1876=DIRECTION('',(0.,0.,1.));
#1877=DIRECTION('',(1.,0.,0.));
#1878=AXIS2_PLACEMENT_3D('',#1875,#1876,#1877);
#1879=CYLINDRICAL_SURFACE('',#1878,2.12132034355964);
#1880=ORIENTED_EDGE('',*,*,#153,.T.);
#1881=ORIENTED_EDGE('',*,*,#1870,.F.);
#1882=ORIENTED_EDGE('',*,*,#743,.F.);
#1883=DIRECTION('',(0.,0.,1.));
#1884=VECTOR('',#1883,1.);
#1885=CARTESIAN_POINT('',(100.,45.4500000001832,0.));
#1886=LINE('',#1885,#1884);
#1887=EDGE_CURVE('E441',#735,#152,#1886,.T.);
#1888=ORIENTED_EDGE('',*,*,#1887,.T.);
#1889=EDGE_LOOP('',(#1880,#1881,#1882,#1888));
#1890=FACE_BOUND('',#1889,.T.);
#1891=ADVANCED_FACE('F1144',(#1890),#1879,.F.);
#1892=CARTESIAN_POINT('',(100.,54.5500000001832,0.));
#1893=DIRECTION('',(-1.,0.,0.));
#1894=DIRECTION('',(0.,-1.,0.));
#1895=AXIS2_PLACEMENT_3D('',#1892,#1893,#1894);
#1896=PLANE('',#1895);
#1897=ORIENTED_EDGE('',*,*,#161,.T.);
#1898=ORIENTED_EDGE('',*,*,#1887,.F.);
#1899=ORIENTED_EDGE('',*,*,#736,.F.);
#1900=DIRECTION('',(0.,0.,1.));
#1901=VECTOR('',#1900,1.);
#1902=CARTESIAN_POINT('',(100.,54.5500000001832,0.));
#1903=LINE('',#1902,#1901);
#1904=EDGE_CURVE('E481',#727,#160,#1903,.T.);
#1905=ORIENTED_EDGE('',*,*,#1904,.T.);
#1906=EDGE_LOOP('',(#1897,#1898,#1899,#1905));
#1907=FACE_BOUND('',#1906,.T.);
#1908=ADVANCED_FACE('F1135',(#1907),#1896,.F.);
#1909=CARTESIAN_POINT('',(101.5,56.0500000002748,0.));
#1910=DIRECTION('',(0.,0.,1.));
#1911=DIRECTION('',(1.,0.,0.));
#1912=AXIS2_PLACEMENT_3D('',#1909,#1910,#1911);
#1913=CYLINDRICAL_SURFACE('',#1912,2.1213203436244);
#1914=ORIENTED_EDGE('',*,*,#170,.F.);
#1915=ORIENTED_EDGE('',*,*,#1904,.F.);
#1916=ORIENTED_EDGE('',*,*,#728,.T.);
#1917=DIRECTION('',(0.,0.,1.));
#1918=VECTOR('',#1917,1.);
#1919=CARTESIAN_POINT('',(103.,57.5500000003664,0.));
#1920=LINE('',#1919,#1918);
#1921=EDGE_CURVE('E479',#718,#169,#1920,.T.);
#1922=ORIENTED_EDGE('',*,*,#1921,.T.);
#1923=EDGE_LOOP('',(#1914,#1915,#1916,#1922));
#1924=FACE_BOUND('',#1923,.T.);
#1925=ADVANCED_FACE('F1126',(#1924),#1913,.F.);
#1926=CARTESIAN_POINT('',(112.1,57.5500000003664,0.));
#1927=DIRECTION('',(0.,1.,0.));
#1928=DIRECTION('',(0.,0.,1.));
#1929=AXIS2_PLACEMENT_3D('',#1926,#1927,#1928);
#1930=PLANE('',#1929);
#1931=ORIENTED_EDGE('',*,*,#178,.T.);
#1932=ORIENTED_EDGE('',*,*,#1921,.F.);
#1933=ORIENTED_EDGE('',*,*,#719,.F.);
#1934=DIRECTION('',(0.,0.,1.));
#1935=VECTOR('',#1934,1.);
#1936=CARTESIAN_POINT('',(112.1,57.5500000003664,0.));
#1937=LINE('',#1936,#1935);
#1938=EDGE_CURVE('E477',#710,#177,#1937,.T.);
#1939=ORIENTED_EDGE('',*,*,#1938,.T.);
#1940=EDGE_LOOP('',(#1931,#1932,#1933,#1939));
#1941=FACE_BOUND('',#1940,.T.);
#1942=ADVANCED_FACE('F1117',(#1941),#1930,.F.);
#1943=CARTESIAN_POINT('',(113.6,56.0500000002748,0.));
#1944=DIRECTION('',(0.,0.,1.));
#1945=DIRECTION('',(1.,0.,0.));
#1946=AXIS2_PLACEMENT_3D('',#1943,#1944,#1945);
#1947=CYLINDRICAL_SURFACE('',#1946,2.12132034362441);
#1948=ORIENTED_EDGE('',*,*,#187,.T.);
#1949=ORIENTED_EDGE('',*,*,#1938,.F.);
#1950=ORIENTED_EDGE('',*,*,#711,.F.);
#1951=DIRECTION('',(0.,0.,1.));
#1952=VECTOR('',#1951,1.);
#1953=CARTESIAN_POINT('',(115.1,54.5500000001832,0.));
#1954=LINE('',#1953,#1952);
#1955=EDGE_CURVE('E475',#701,#186,#1954,.T.);
#1956=ORIENTED_EDGE('',*,*,#1955,.T.);
#1957=EDGE_LOOP('',(#1948,#1949,#1950,#1956));
#1958=FACE_BOUND('',#1957,.T.);
#1959=ADVANCED_FACE('F1108',(#1958),#1947,.F.);
#1960=CARTESIAN_POINT('',(115.1,45.4500000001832,0.));
#1961=DIRECTION('',(1.,0.,0.));
#1962=DIRECTION('',(0.,0.,-1.));
#1963=AXIS2_PLACEMENT_3D('',#1960,#1961,#1962);
#1964=PLANE('',#1963);
#1965=ORIENTED_EDGE('',*,*,#193,.T.);
#1966=ORIENTED_EDGE('',*,*,#1955,.F.);
#1967=ORIENTED_EDGE('',*,*,#702,.F.);
#1968=DIRECTION('',(0.,0.,1.));
#1969=VECTOR('',#1968,1.);
#1970=CARTESIAN_POINT('',(115.1,45.4500000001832,0.));
#1971=LINE('',#1970,#1969);
#1972=EDGE_CURVE('E473',#693,#135,#1971,.T.);
#1973=ORIENTED_EDGE('',*,*,#1972,.T.);
#1974=EDGE_LOOP('',(#1965,#1966,#1967,#1973));
#1975=FACE_BOUND('',#1974,.T.);
#1976=ADVANCED_FACE('F1099',(#1975),#1964,.F.);
#1977=CARTESIAN_POINT('',(113.6,43.9500000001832,0.));
#1978=DIRECTION('',(0.,0.,1.));
#1979=DIRECTION('',(1.,0.,0.));
#1980=AXIS2_PLACEMENT_3D('',#1977,#1978,#1979);
#1981=CYLINDRICAL_SURFACE('',#1980,2.12132034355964);
#1982=ORIENTED_EDGE('',*,*,#136,.T.);
#1983=ORIENTED_EDGE('',*,*,#1972,.F.);
#1984=ORIENTED_EDGE('',*,*,#694,.F.);
#1985=ORIENTED_EDGE('',*,*,#1863,.T.);
#1986=EDGE_LOOP('',(#1982,#1983,#1984,#1985));
#1987=FACE_BOUND('',#1986,.T.);
#1988=ADVANCED_FACE('F1091',(#1987),#1981,.F.);
#1989=CARTESIAN_POINT('',(113.6,25.9500000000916,0.));
#1990=DIRECTION('',(0.,0.,1.));
#1991=DIRECTION('',(1.,0.,0.));
#1992=AXIS2_PLACEMENT_3D('',#1989,#1990,#1991);
#1993=CYLINDRICAL_SURFACE('',#1992,2.12132034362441);
#1994=ORIENTED_EDGE('',*,*,#74,.T.);
#1995=DIRECTION('',(0.,0.,1.));
#1996=VECTOR('',#1995,1.);
#1997=CARTESIAN_POINT('',(112.1,27.4500000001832,0.));
#1998=LINE('',#1997,#1996);
#1999=EDGE_CURVE('E450',#615,#62,#1998,.T.);
#2000=ORIENTED_EDGE('',*,*,#1999,.F.);
#2001=ORIENTED_EDGE('',*,*,#616,.F.);
#2002=DIRECTION('',(0.,0.,1.));
#2003=VECTOR('',#2002,1.);
#2004=CARTESIAN_POINT('',(115.1,24.45,0.));
#2005=LINE('',#2004,#2003);
#2006=EDGE_CURVE('E412',#613,#73,#2005,.T.);
#2007=ORIENTED_EDGE('',*,*,#2006,.T.);
#2008=EDGE_LOOP('',(#1994,#2000,#2001,#2007));
#2009=FACE_BOUND('',#2008,.T.);
#2010=ADVANCED_FACE('F414',(#2009),#1993,.F.);
#2011=CARTESIAN_POINT('',(115.1,15.35,0.));
#2012=DIRECTION('',(1.,0.,0.));
#2013=DIRECTION('',(0.,0.,-1.));
#2014=AXIS2_PLACEMENT_3D('',#2011,#2012,#2013);
#2015=PLANE('',#2014);
#2016=ORIENTED_EDGE('',*,*,#82,.T.);
#2017=ORIENTED_EDGE('',*,*,#2006,.F.);
#2018=ORIENTED_EDGE('',*,*,#673,.F.);
#2019=DIRECTION('',(0.,0.,1.));
#2020=VECTOR('',#2019,1.);
#2021=CARTESIAN_POINT('',(115.1,15.35,0.));
#2022=LINE('',#2021,#2020);
#2023=EDGE_CURVE('E423',#666,#81,#2022,.T.);
#2024=ORIENTED_EDGE('',*,*,#2023,.T.);
#2025=EDGE_LOOP('',(#2016,#2017,#2018,#2024));
#2026=FACE_BOUND('',#2025,.T.);
#2027=ADVANCED_FACE('F428',(#2026),#2015,.F.);
#2028=CARTESIAN_POINT('',(113.6,13.85,0.));
#2029=DIRECTION('',(0.,0.,1.));
#2030=DIRECTION('',(1.,0.,0.));
#2031=AXIS2_PLACEMENT_3D('',#2028,#2029,#2030);
#2032=CYLINDRICAL_SURFACE('',#2031,2.12132034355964);
#2033=ORIENTED_EDGE('',*,*,#91,.T.);
#2034=ORIENTED_EDGE('',*,*,#2023,.F.);
#2035=ORIENTED_EDGE('',*,*,#667,.F.);
#2036=DIRECTION('',(0.,0.,1.));
#2037=VECTOR('',#2036,1.);
#2038=CARTESIAN_POINT('',(112.1,12.35,0.));
#2039=LINE('',#2038,#2037);
#2040=EDGE_CURVE('E1668',#657,#90,#2039,.T.);
#2041=ORIENTED_EDGE('',*,*,#2040,.T.);
#2042=EDGE_LOOP('',(#2033,#2034,#2035,#2041));
#2043=FACE_BOUND('',#2042,.T.);
#2044=ADVANCED_FACE('F1067',(#2043),#2032,.F.);
#2045=CARTESIAN_POINT('',(103.,12.35,0.));
#2046=DIRECTION('',(0.,-1.,0.));
#2047=DIRECTION('',(0.,0.,-1.));
#2048=AXIS2_PLACEMENT_3D('',#2045,#2046,#2047);
#2049=PLANE('',#2048);
#2050=ORIENTED_EDGE('',*,*,#99,.T.);
#2051=ORIENTED_EDGE('',*,*,#2040,.F.);
#2052=ORIENTED_EDGE('',*,*,#658,.F.);
#2053=DIRECTION('',(0.,0.,1.));
#2054=VECTOR('',#2053,1.);
#2055=CARTESIAN_POINT('',(103.,12.35,0.));
#2056=LINE('',#2055,#2054);
#2057=EDGE_CURVE('E1697',#649,#98,#2056,.T.);
#2058=ORIENTED_EDGE('',*,*,#2057,.T.);
#2059=EDGE_LOOP('',(#2050,#2051,#2052,#2058));
#2060=FACE_BOUND('',#2059,.T.);
#2061=ADVANCED_FACE('F1058',(#2060),#2049,.F.);
#2062=CARTESIAN_POINT('',(101.5,13.85,0.));
#2063=DIRECTION('',(0.,0.,1.));
#2064=DIRECTION('',(1.,0.,0.));
#2065=AXIS2_PLACEMENT_3D('',#2062,#2063,#2064);
#2066=CYLINDRICAL_SURFACE('',#2065,2.12132034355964);
#2067=ORIENTED_EDGE('',*,*,#108,.T.);
#2068=ORIENTED_EDGE('',*,*,#2057,.F.);
#2069=ORIENTED_EDGE('',*,*,#650,.F.);
#2070=DIRECTION('',(0.,0.,1.));
#2071=VECTOR('',#2070,1.);
#2072=CARTESIAN_POINT('',(100.,15.35,0.));
#2073=LINE('',#2072,#2071);
#2074=EDGE_CURVE('E1695',#640,#107,#2073,.T.);
#2075=ORIENTED_EDGE('',*,*,#2074,.T.);
#2076=EDGE_LOOP('',(#2067,#2068,#2069,#2075));
#2077=FACE_BOUND('',#2076,.T.);
#2078=ADVANCED_FACE('F1049',(#2077),#2066,.F.);
#2079=CARTESIAN_POINT('',(100.,24.45,0.));
#2080=DIRECTION('',(-1.,0.,0.));
#2081=DIRECTION('',(0.,0.,1.));
#2082=AXIS2_PLACEMENT_3D('',#2079,#2080,#2081);
#2083=PLANE('',#2082);
#2084=ORIENTED_EDGE('',*,*,#116,.T.);
#2085=ORIENTED_EDGE('',*,*,#2074,.F.);
#2086=ORIENTED_EDGE('',*,*,#641,.F.);
#2087=DIRECTION('',(0.,0.,1.));
#2088=VECTOR('',#2087,1.);
#2089=CARTESIAN_POINT('',(100.,24.45,0.));
#2090=LINE('',#2089,#2088);
#2091=EDGE_CURVE('E1683',#632,#115,#2090,.T.);
#2092=ORIENTED_EDGE('',*,*,#2091,.T.);
#2093=EDGE_LOOP('',(#2084,#2085,#2086,#2092));
#2094=FACE_BOUND('',#2093,.T.);
#2095=ADVANCED_FACE('F1040',(#2094),#2083,.F.);
#2096=CARTESIAN_POINT('',(101.5,25.9500000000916,0.));
#2097=DIRECTION('',(0.,0.,1.));
#2098=DIRECTION('',(1.,0.,0.));
#2099=AXIS2_PLACEMENT_3D('',#2096,#2097,#2098);
#2100=CYLINDRICAL_SURFACE('',#2099,2.12132034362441);
#2101=ORIENTED_EDGE('',*,*,#123,.F.);
#2102=ORIENTED_EDGE('',*,*,#2091,.F.);
#2103=ORIENTED_EDGE('',*,*,#633,.T.);
#2104=DIRECTION('',(0.,0.,1.));
#2105=VECTOR('',#2104,1.);
#2106=CARTESIAN_POINT('',(103.,27.4500000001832,0.));
#2107=LINE('',#2106,#2105);
#2108=EDGE_CURVE('E1685',#623,#64,#2107,.T.);
#2109=ORIENTED_EDGE('',*,*,#2108,.T.);
#2110=EDGE_LOOP('',(#2101,#2102,#2103,#2109));
#2111=FACE_BOUND('',#2110,.T.);
#2112=ADVANCED_FACE('F1031',(#2111),#2100,.F.);
#2113=CARTESIAN_POINT('',(112.1,27.4500000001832,0.));
#2114=DIRECTION('',(0.,1.,0.));
#2115=DIRECTION('',(0.,0.,1.));
#2116=AXIS2_PLACEMENT_3D('',#2113,#2114,#2115);
#2117=PLANE('',#2116);
#2118=ORIENTED_EDGE('',*,*,#65,.T.);
#2119=ORIENTED_EDGE('',*,*,#2108,.F.);
#2120=ORIENTED_EDGE('',*,*,#624,.F.);
#2121=ORIENTED_EDGE('',*,*,#1999,.T.);
#2122=EDGE_LOOP('',(#2118,#2119,#2120,#2121));
#2123=FACE_BOUND('',#2122,.T.);
#2124=ADVANCED_FACE('F1022',(#2123),#2117,.F.);
#2125=CARTESIAN_POINT('',(554.5,69.5,0.));
#2126=DIRECTION('',(0.,0.,1.));
#2127=DIRECTION('',(1.,0.,0.));
#2128=AXIS2_PLACEMENT_3D('',#2125,#2126,#2127);
#2129=CYLINDRICAL_SURFACE('',#2128,3.52500000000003);
#2130=ORIENTED_EDGE('',*,*,#603,.F.);
#2131=EDGE_LOOP('',(#2130));
#2132=FACE_BOUND('',#2131,.T.);
#2133=ORIENTED_EDGE('',*,*,#53,.T.);
#2134=EDGE_LOOP('',(#2133));
#2135=FACE_BOUND('',#2134,.T.);
#2136=ADVANCED_FACE('F1013',(#2132,#2135),#2129,.F.);
#2137=CARTESIAN_POINT('',(554.5,25.,7.5));
#2138=DIRECTION('',(0.,0.,1.));
#2139=DIRECTION('',(1.,0.,0.));
#2140=AXIS2_PLACEMENT_3D('',#2137,#2138,#2139);
#2141=CYLINDRICAL_SURFACE('',#2140,5.025);
#2142=CARTESIAN_POINT('',(554.5,25.,7.5));
#2143=DIRECTION('',(0.,0.,1.));
#2144=DIRECTION('',(1.,0.,0.));
#2145=AXIS2_PLACEMENT_3D('',#2142,#2143,#2144);
#2146=CIRCLE('',#2145,5.025);
#2147=CARTESIAN_POINT('',(559.525,25.,7.5));
#2148=VERTEX_POINT('',#2147);
#2149=EDGE_CURVE('E1704',#2148,#2148,#2146,.T.);
#2150=ORIENTED_EDGE('',*,*,#2149,.F.);
#2151=EDGE_LOOP('',(#2150));
#2152=FACE_BOUND('',#2151,.T.);
#2153=ORIENTED_EDGE('',*,*,#42,.T.);
#2154=EDGE_LOOP('',(#2153));
#2155=FACE_BOUND('',#2154,.T.);
#2156=ADVANCED_FACE('F1004',(#2152,#2155),#2141,.F.);
#2157=CARTESIAN_POINT('',(554.5,25.,7.5));
#2158=DIRECTION('',(0.,0.,1.));
#2159=DIRECTION('',(1.,0.,0.));
#2160=AXIS2_PLACEMENT_3D('',#2157,#2158,#2159);
#2161=PLANE('',#2160);
#2162=ORIENTED_EDGE('',*,*,#2149,.T.);
#2163=EDGE_LOOP('',(#2162));
#2164=FACE_BOUND('',#2163,.T.);
#2165=ADVANCED_FACE('F995',(#2164),#2161,.T.);
#2166=CARTESIAN_POINT('',(45.5,25.,7.5));
#2167=DIRECTION('',(0.,0.,1.));
#2168=DIRECTION('',(1.,0.,0.));
#2169=AXIS2_PLACEMENT_3D('',#2166,#2167,#2168);
#2170=CYLINDRICAL_SURFACE('',#2169,5.025);
#2171=CARTESIAN_POINT('',(45.5,25.,7.5));
#2172=DIRECTION('',(0.,0.,1.));
#2173=DIRECTION('',(1.,0.,0.));
#2174=AXIS2_PLACEMENT_3D('',#2171,#2172,#2173);
#2175=CIRCLE('',#2174,5.025);
#2176=CARTESIAN_POINT('',(50.5249999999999,25.,7.5));
#2177=VERTEX_POINT('',#2176);
#2178=EDGE_CURVE('E1710',#2177,#2177,#2175,.T.);
#2179=ORIENTED_EDGE('',*,*,#2178,.F.);
#2180=EDGE_LOOP('',(#2179));
#2181=FACE_BOUND('',#2180,.T.);
#2182=ORIENTED_EDGE('',*,*,#31,.T.);
#2183=EDGE_LOOP('',(#2182));
#2184=FACE_BOUND('',#2183,.T.);
#2185=ADVANCED_FACE('F986',(#2181,#2184),#2170,.F.);
#2186=CARTESIAN_POINT('',(45.5,25.,7.5));
#2187=DIRECTION('',(0.,0.,1.));
#2188=DIRECTION('',(1.,0.,0.));
#2189=AXIS2_PLACEMENT_3D('',#2186,#2187,#2188);
#2190=PLANE('',#2189);
#2191=ORIENTED_EDGE('',*,*,#2178,.T.);
#2192=EDGE_LOOP('',(#2191));
#2193=FACE_BOUND('',#2192,.T.);
#2194=ADVANCED_FACE('F957',(#2193),#2190,.T.);
#2195=CARTESIAN_POINT('',(447.,13.7043263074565,15.));
#2196=DIRECTION('',(0.,0.,1.));
#2197=DIRECTION('',(1.,0.,0.));
#2198=AXIS2_PLACEMENT_3D('',#2195,#2196,#2197);
#2199=CYLINDRICAL_SURFACE('',#2198,3.);
#2200=ORIENTED_EDGE('',*,*,#516,.F.);
#2201=ORIENTED_EDGE('',*,*,#1212,.F.);
#2202=ORIENTED_EDGE('',*,*,#1002,.F.);
#2203=ORIENTED_EDGE('',*,*,#1234,.F.);
#2204=EDGE_LOOP('',(#2200,#2201,#2202,#2203));
#2205=FACE_BOUND('',#2204,.T.);
#2206=ADVANCED_FACE('F886',(#2205),#2199,.F.);
#2207=CARTESIAN_POINT('',(453.,3.,15.));
#2208=DIRECTION('',(0.,0.,-1.));
#2209=DIRECTION('',(-1.,0.,0.));
#2210=AXIS2_PLACEMENT_3D('',#2207,#2208,#2209);
#2211=CYLINDRICAL_SURFACE('',#2210,3.);
#2212=ORIENTED_EDGE('',*,*,#435,.F.);
#2213=ORIENTED_EDGE('',*,*,#1241,.F.);
#2214=ORIENTED_EDGE('',*,*,#985,.F.);
#2215=ORIENTED_EDGE('',*,*,#1256,.F.);
#2216=EDGE_LOOP('',(#2212,#2213,#2214,#2215));
#2217=FACE_BOUND('',#2216,.T.);
#2218=ADVANCED_FACE('F895',(#2217),#2211,.T.);
#2219=CARTESIAN_POINT('',(153.,13.7043263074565,15.));
#2220=DIRECTION('',(0.,0.,1.));
#2221=DIRECTION('',(1.,0.,0.));
#2222=AXIS2_PLACEMENT_3D('',#2219,#2220,#2221);
#2223=CYLINDRICAL_SURFACE('',#2222,3.);
#2224=ORIENTED_EDGE('',*,*,#501,.F.);
#2225=ORIENTED_EDGE('',*,*,#1190,.F.);
#2226=ORIENTED_EDGE('',*,*,#1019,.F.);
#2227=ORIENTED_EDGE('',*,*,#1219,.F.);
#2228=EDGE_LOOP('',(#2224,#2225,#2226,#2227));
#2229=FACE_BOUND('',#2228,.T.);
#2230=ADVANCED_FACE('F878',(#2229),#2223,.F.);
#2231=CARTESIAN_POINT('',(147.,3.,15.));
#2232=DIRECTION('',(0.,0.,-1.));
#2233=DIRECTION('',(-1.,0.,0.));
#2234=AXIS2_PLACEMENT_3D('',#2231,#2232,#2233);
#2235=CYLINDRICAL_SURFACE('',#2234,3.);
#2236=ORIENTED_EDGE('',*,*,#484,.F.);
#2237=ORIENTED_EDGE('',*,*,#1173,.F.);
#2238=ORIENTED_EDGE('',*,*,#1036,.F.);
#2239=ORIENTED_EDGE('',*,*,#1197,.F.);
#2240=EDGE_LOOP('',(#2236,#2237,#2238,#2239));
#2241=FACE_BOUND('',#2240,.T.);
#2242=ADVANCED_FACE('F37',(#2241),#2235,.T.);
#2243=CLOSED_SHELL('',(#590,#1140,#1162,#1179,#1201,#1223,#1245,#1267,#1284,#1296,#1318,#1335,
#1352,#1369,#1386,#1403,#1420,#1432,#1454,#1471,#1488,#1505,#1522,#1539,#1556,#1568,#1590,#1607,
#1624,#1641,#1658,#1675,#1692,#1704,#1716,#1738,#1755,#1772,#1789,#1806,#1823,#1840,#1852,#1874,
#1891,#1908,#1925,#1942,#1959,#1976,#1988,#2010,#2027,#2044,#2061,#2078,#2095,#2112,#2124,#2136,
#2156,#2165,#2185,#2194,#2206,#2218,#2230,#2242));
#2244=MANIFOLD_SOLID_BREP('B2',#2243);
#2245=ADVANCED_BREP_SHAPE_REPRESENTATION('',(#18,#2244),#14);
#2246=SHAPE_DEFINITION_REPRESENTATION(#9,#2245);
ENDSEC;
END-ISO-10303-21;
